VERSION 5.7 ;
  NOWIREEXTENSIONATPIN ON ;
  DIVIDERCHAR "/" ;
  BUSBITCHARS "[]" ;
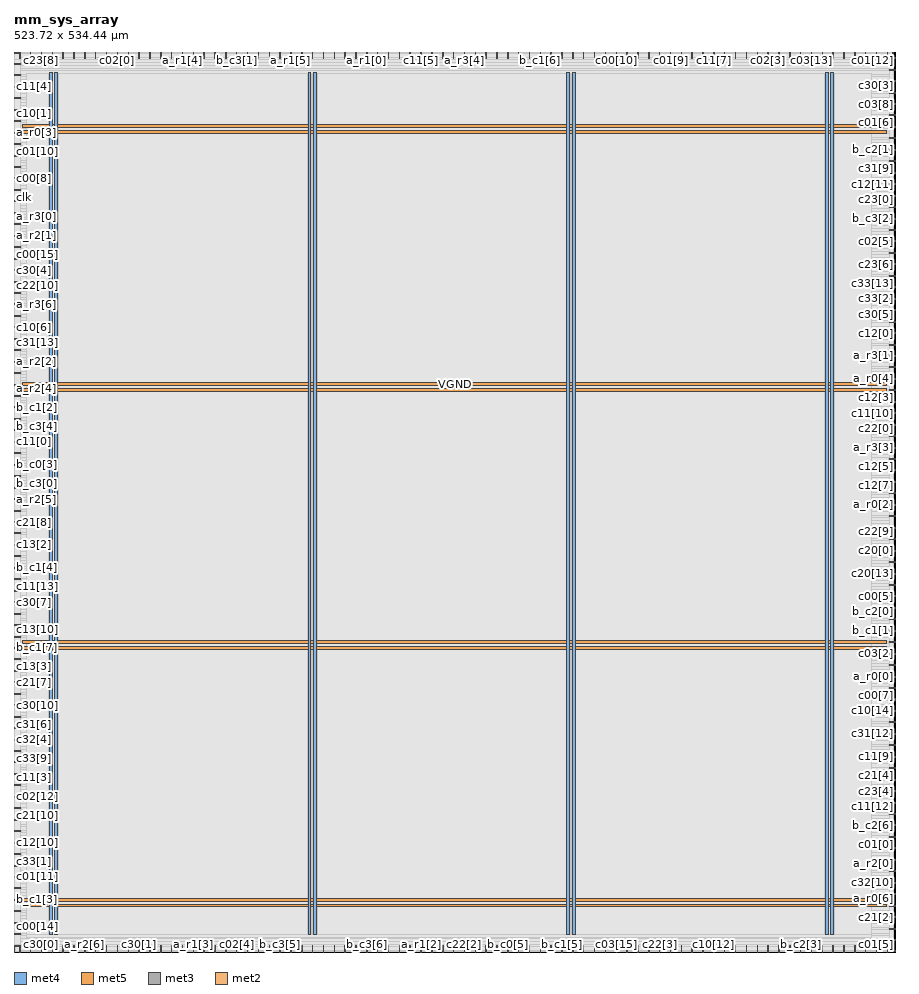
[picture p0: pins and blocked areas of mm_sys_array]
MACRO mm_sys_array
  CLASS BLOCK ;
  FOREIGN mm_sys_array ;
  ORIGIN 0.000 0.000 ;
  SIZE 523.720 BY 534.440 ;
  PIN VGND
    DIRECTION INOUT ;
    USE GROUND ;
    PORT
      LAYER met4 ;
        RECT 24.340 10.640 25.940 522.480 ;
    END
    PORT
      LAYER met4 ;
        RECT 177.940 10.640 179.540 522.480 ;
    END
    PORT
      LAYER met4 ;
        RECT 331.540 10.640 333.140 522.480 ;
    END
    PORT
      LAYER met4 ;
        RECT 485.140 10.640 486.740 522.480 ;
    END
    PORT
      LAYER met5 ;
        RECT 5.280 30.030 518.200 31.630 ;
    END
    PORT
      LAYER met5 ;
        RECT 5.280 183.210 518.200 184.810 ;
    END
    PORT
      LAYER met5 ;
        RECT 5.280 336.390 518.200 337.990 ;
    END
    PORT
      LAYER met5 ;
        RECT 5.280 489.570 518.200 491.170 ;
    END
  END VGND
  PIN VPWR
    DIRECTION INOUT ;
    USE POWER ;
    PORT
      LAYER met4 ;
        RECT 21.040 10.640 22.640 522.480 ;
    END
    PORT
      LAYER met4 ;
        RECT 174.640 10.640 176.240 522.480 ;
    END
    PORT
      LAYER met4 ;
        RECT 328.240 10.640 329.840 522.480 ;
    END
    PORT
      LAYER met4 ;
        RECT 481.840 10.640 483.440 522.480 ;
    END
    PORT
      LAYER met5 ;
        RECT 5.280 26.730 518.200 28.330 ;
    END
    PORT
      LAYER met5 ;
        RECT 5.280 179.910 518.200 181.510 ;
    END
    PORT
      LAYER met5 ;
        RECT 5.280 333.090 518.200 334.690 ;
    END
    PORT
      LAYER met5 ;
        RECT 5.280 486.270 518.200 487.870 ;
    END
  END VPWR
  PIN a_r0[0]
    DIRECTION INPUT ;
    USE SIGNAL ;
    ANTENNAGATEAREA 0.426000 ;
    PORT
      LAYER met3 ;
        RECT 519.720 163.240 523.720 163.840 ;
    END
  END a_r0[0]
  PIN a_r0[1]
    DIRECTION INPUT ;
    USE SIGNAL ;
    ANTENNAGATEAREA 0.247500 ;
    PORT
      LAYER met3 ;
        RECT 519.720 217.640 523.720 218.240 ;
    END
  END a_r0[1]
  PIN a_r0[2]
    DIRECTION INPUT ;
    USE SIGNAL ;
    ANTENNAGATEAREA 0.247500 ;
    PORT
      LAYER met3 ;
        RECT 519.720 265.240 523.720 265.840 ;
    END
  END a_r0[2]
  PIN a_r0[3]
    DIRECTION INPUT ;
    USE SIGNAL ;
    ANTENNAGATEAREA 0.426000 ;
    PORT
      LAYER met3 ;
        RECT 0.000 486.240 4.000 486.840 ;
    END
  END a_r0[3]
  PIN a_r0[4]
    DIRECTION INPUT ;
    USE SIGNAL ;
    ANTENNAGATEAREA 0.426000 ;
    PORT
      LAYER met3 ;
        RECT 519.720 340.040 523.720 340.640 ;
    END
  END a_r0[4]
  PIN a_r0[5]
    DIRECTION INPUT ;
    USE SIGNAL ;
    ANTENNAGATEAREA 0.247500 ;
    PORT
      LAYER met3 ;
        RECT 0.000 234.640 4.000 235.240 ;
    END
  END a_r0[5]
  PIN a_r0[6]
    DIRECTION INPUT ;
    USE SIGNAL ;
    ANTENNAGATEAREA 0.247500 ;
    PORT
      LAYER met3 ;
        RECT 519.720 27.240 523.720 27.840 ;
    END
  END a_r0[6]
  PIN a_r0[7]
    DIRECTION INPUT ;
    USE SIGNAL ;
    ANTENNAGATEAREA 0.247500 ;
    PORT
      LAYER met3 ;
        RECT 519.720 6.840 523.720 7.440 ;
    END
  END a_r0[7]
  PIN a_r1[0]
    DIRECTION INPUT ;
    USE SIGNAL ;
    ANTENNAGATEAREA 0.196500 ;
    PORT
      LAYER met2 ;
        RECT 209.390 530.440 209.670 534.440 ;
    END
  END a_r1[0]
  PIN a_r1[1]
    DIRECTION INPUT ;
    USE SIGNAL ;
    ANTENNAGATEAREA 0.213000 ;
    PORT
      LAYER met3 ;
        RECT 0.000 200.640 4.000 201.240 ;
    END
  END a_r1[1]
  PIN a_r1[2]
    DIRECTION INPUT ;
    USE SIGNAL ;
    ANTENNAGATEAREA 0.213000 ;
    PORT
      LAYER met2 ;
        RECT 241.590 0.000 241.870 4.000 ;
    END
  END a_r1[2]
  PIN a_r1[3]
    DIRECTION INPUT ;
    USE SIGNAL ;
    ANTENNAGATEAREA 0.159000 ;
    PORT
      LAYER met2 ;
        RECT 106.350 0.000 106.630 4.000 ;
    END
  END a_r1[3]
  PIN a_r1[4]
    DIRECTION INPUT ;
    USE SIGNAL ;
    ANTENNAGATEAREA 0.196500 ;
    PORT
      LAYER met2 ;
        RECT 99.910 530.440 100.190 534.440 ;
    END
  END a_r1[4]
  PIN a_r1[5]
    DIRECTION INPUT ;
    USE SIGNAL ;
    ANTENNAGATEAREA 0.196500 ;
    PORT
      LAYER met2 ;
        RECT 164.310 530.440 164.590 534.440 ;
    END
  END a_r1[5]
  PIN a_r1[6]
    DIRECTION INPUT ;
    USE SIGNAL ;
    ANTENNAGATEAREA 0.159000 ;
    PORT
      LAYER met2 ;
        RECT 144.990 0.000 145.270 4.000 ;
    END
  END a_r1[6]
  PIN a_r1[7]
    DIRECTION INPUT ;
    USE SIGNAL ;
    ANTENNAGATEAREA 0.159000 ;
    PORT
      LAYER met2 ;
        RECT 138.550 0.000 138.830 4.000 ;
    END
  END a_r1[7]
  PIN a_r2[0]
    DIRECTION INPUT ;
    USE SIGNAL ;
    ANTENNAGATEAREA 0.213000 ;
    PORT
      LAYER met3 ;
        RECT 519.720 47.640 523.720 48.240 ;
    END
  END a_r2[0]
  PIN a_r2[1]
    DIRECTION INPUT ;
    USE SIGNAL ;
    ANTENNAGATEAREA 0.196500 ;
    PORT
      LAYER met3 ;
        RECT 0.000 425.040 4.000 425.640 ;
    END
  END a_r2[1]
  PIN a_r2[2]
    DIRECTION INPUT ;
    USE SIGNAL ;
    ANTENNAGATEAREA 0.196500 ;
    PORT
      LAYER met3 ;
        RECT 0.000 350.240 4.000 350.840 ;
    END
  END a_r2[2]
  PIN a_r2[3]
    DIRECTION INPUT ;
    USE SIGNAL ;
    ANTENNAGATEAREA 0.196500 ;
    PORT
      LAYER met2 ;
        RECT 22.630 0.000 22.910 4.000 ;
    END
  END a_r2[3]
  PIN a_r2[4]
    DIRECTION INPUT ;
    USE SIGNAL ;
    ANTENNAGATEAREA 0.196500 ;
    PORT
      LAYER met3 ;
        RECT 0.000 329.840 4.000 330.440 ;
    END
  END a_r2[4]
  PIN a_r2[5]
    DIRECTION INPUT ;
    USE SIGNAL ;
    ANTENNAGATEAREA 0.196500 ;
    PORT
      LAYER met3 ;
        RECT 0.000 268.640 4.000 269.240 ;
    END
  END a_r2[5]
  PIN a_r2[6]
    DIRECTION INPUT ;
    USE SIGNAL ;
    ANTENNAGATEAREA 0.196500 ;
    PORT
      LAYER met2 ;
        RECT 41.950 0.000 42.230 4.000 ;
    END
  END a_r2[6]
  PIN a_r2[7]
    DIRECTION INPUT ;
    USE SIGNAL ;
    ANTENNAGATEAREA 0.196500 ;
    PORT
      LAYER met2 ;
        RECT 170.750 530.440 171.030 534.440 ;
    END
  END a_r2[7]
  PIN a_r3[0]
    DIRECTION INPUT ;
    USE SIGNAL ;
    ANTENNAGATEAREA 0.196500 ;
    PORT
      LAYER met3 ;
        RECT 0.000 431.840 4.000 432.440 ;
    END
  END a_r3[0]
  PIN a_r3[1]
    DIRECTION INPUT ;
    USE SIGNAL ;
    ANTENNAGATEAREA 0.159000 ;
    PORT
      LAYER met3 ;
        RECT 519.720 353.640 523.720 354.240 ;
    END
  END a_r3[1]
  PIN a_r3[2]
    DIRECTION INPUT ;
    USE SIGNAL ;
    ANTENNAGATEAREA 0.196500 ;
    PORT
      LAYER met3 ;
        RECT 0.000 309.440 4.000 310.040 ;
    END
  END a_r3[2]
  PIN a_r3[3]
    DIRECTION INPUT ;
    USE SIGNAL ;
    ANTENNAGATEAREA 0.213000 ;
    PORT
      LAYER met3 ;
        RECT 519.720 299.240 523.720 299.840 ;
    END
  END a_r3[3]
  PIN a_r3[4]
    DIRECTION INPUT ;
    USE SIGNAL ;
    ANTENNAGATEAREA 0.213000 ;
    PORT
      LAYER met2 ;
        RECT 267.350 530.440 267.630 534.440 ;
    END
  END a_r3[4]
  PIN a_r3[5]
    DIRECTION INPUT ;
    USE SIGNAL ;
    ANTENNAGATEAREA 0.159000 ;
    PORT
      LAYER met3 ;
        RECT 519.720 380.840 523.720 381.440 ;
    END
  END a_r3[5]
  PIN a_r3[6]
    DIRECTION INPUT ;
    USE SIGNAL ;
    ANTENNAGATEAREA 0.196500 ;
    PORT
      LAYER met3 ;
        RECT 0.000 384.240 4.000 384.840 ;
    END
  END a_r3[6]
  PIN a_r3[7]
    DIRECTION INPUT ;
    USE SIGNAL ;
    ANTENNAGATEAREA 0.213000 ;
    PORT
      LAYER met2 ;
        RECT 3.310 0.000 3.590 4.000 ;
    END
  END a_r3[7]
  PIN b_c0[0]
    DIRECTION INPUT ;
    USE SIGNAL ;
    ANTENNAGATEAREA 0.247500 ;
    PORT
      LAYER met2 ;
        RECT 402.590 0.000 402.870 4.000 ;
    END
  END b_c0[0]
  PIN b_c0[1]
    DIRECTION INPUT ;
    USE SIGNAL ;
    ANTENNAGATEAREA 0.426000 ;
    PORT
      LAYER met2 ;
        RECT 93.470 530.440 93.750 534.440 ;
    END
  END b_c0[1]
  PIN b_c0[2]
    DIRECTION INPUT ;
    USE SIGNAL ;
    ANTENNAGATEAREA 0.159000 ;
    PORT
      LAYER met3 ;
        RECT 519.720 326.440 523.720 327.040 ;
    END
  END b_c0[2]
  PIN b_c0[3]
    DIRECTION INPUT ;
    USE SIGNAL ;
    ANTENNAGATEAREA 0.213000 ;
    PORT
      LAYER met3 ;
        RECT 0.000 289.040 4.000 289.640 ;
    END
  END b_c0[3]
  PIN b_c0[4]
    DIRECTION INPUT ;
    USE SIGNAL ;
    ANTENNAGATEAREA 0.247500 ;
    PORT
      LAYER met3 ;
        RECT 0.000 261.840 4.000 262.440 ;
    END
  END b_c0[4]
  PIN b_c0[5]
    DIRECTION INPUT ;
    USE SIGNAL ;
    ANTENNAGATEAREA 0.213000 ;
    PORT
      LAYER met2 ;
        RECT 293.110 0.000 293.390 4.000 ;
    END
  END b_c0[5]
  PIN b_c0[6]
    DIRECTION INPUT ;
    USE SIGNAL ;
    ANTENNAGATEAREA 0.247500 ;
    PORT
      LAYER met3 ;
        RECT 0.000 71.440 4.000 72.040 ;
    END
  END b_c0[6]
  PIN b_c0[7]
    DIRECTION INPUT ;
    USE SIGNAL ;
    ANTENNAGATEAREA 0.742500 ;
    PORT
      LAYER met3 ;
        RECT 519.720 54.440 523.720 55.040 ;
    END
  END b_c0[7]
  PIN b_c1[0]
    DIRECTION INPUT ;
    USE SIGNAL ;
    ANTENNAGATEAREA 0.247500 ;
    PORT
      LAYER met3 ;
        RECT 0.000 17.040 4.000 17.640 ;
    END
  END b_c1[0]
  PIN b_c1[1]
    DIRECTION INPUT ;
    USE SIGNAL ;
    ANTENNAGATEAREA 0.196500 ;
    PORT
      LAYER met3 ;
        RECT 519.720 190.440 523.720 191.040 ;
    END
  END b_c1[1]
  PIN b_c1[2]
    DIRECTION INPUT ;
    USE SIGNAL ;
    ANTENNAGATEAREA 0.213000 ;
    PORT
      LAYER met3 ;
        RECT 0.000 323.040 4.000 323.640 ;
    END
  END b_c1[2]
  PIN b_c1[3]
    DIRECTION INPUT ;
    USE SIGNAL ;
    ANTENNAGATEAREA 0.213000 ;
    PORT
      LAYER met3 ;
        RECT 0.000 30.640 4.000 31.240 ;
    END
  END b_c1[3]
  PIN b_c1[4]
    DIRECTION INPUT ;
    USE SIGNAL ;
    ANTENNAGATEAREA 0.159000 ;
    PORT
      LAYER met3 ;
        RECT 0.000 227.840 4.000 228.440 ;
    END
  END b_c1[4]
  PIN b_c1[5]
    DIRECTION INPUT ;
    USE SIGNAL ;
    ANTENNAGATEAREA 0.213000 ;
    PORT
      LAYER met2 ;
        RECT 325.310 0.000 325.590 4.000 ;
    END
  END b_c1[5]
  PIN b_c1[6]
    DIRECTION INPUT ;
    USE SIGNAL ;
    ANTENNAGATEAREA 0.126000 ;
    PORT
      LAYER met2 ;
        RECT 312.430 530.440 312.710 534.440 ;
    END
  END b_c1[6]
  PIN b_c1[7]
    DIRECTION INPUT ;
    USE SIGNAL ;
    ANTENNAGATEAREA 0.159000 ;
    PORT
      LAYER met3 ;
        RECT 0.000 180.240 4.000 180.840 ;
    END
  END b_c1[7]
  PIN b_c2[0]
    DIRECTION INPUT ;
    USE SIGNAL ;
    ANTENNAGATEAREA 0.196500 ;
    PORT
      LAYER met3 ;
        RECT 519.720 197.240 523.720 197.840 ;
    END
  END b_c2[0]
  PIN b_c2[1]
    DIRECTION INPUT ;
    USE SIGNAL ;
    ANTENNAGATEAREA 0.213000 ;
    PORT
      LAYER met3 ;
        RECT 519.720 476.040 523.720 476.640 ;
    END
  END b_c2[1]
  PIN b_c2[2]
    DIRECTION INPUT ;
    USE SIGNAL ;
    ANTENNAGATEAREA 0.213000 ;
    PORT
      LAYER met2 ;
        RECT 67.710 0.000 67.990 4.000 ;
    END
  END b_c2[2]
  PIN b_c2[3]
    DIRECTION INPUT ;
    USE SIGNAL ;
    ANTENNAGATEAREA 0.196500 ;
    PORT
      LAYER met2 ;
        RECT 466.990 0.000 467.270 4.000 ;
    END
  END b_c2[3]
  PIN b_c2[4]
    DIRECTION INPUT ;
    USE SIGNAL ;
    ANTENNAGATEAREA 0.196500 ;
    PORT
      LAYER met3 ;
        RECT 519.720 13.640 523.720 14.240 ;
    END
  END b_c2[4]
  PIN b_c2[5]
    DIRECTION INPUT ;
    USE SIGNAL ;
    ANTENNAGATEAREA 0.213000 ;
    PORT
      LAYER met2 ;
        RECT 318.870 0.000 319.150 4.000 ;
    END
  END b_c2[5]
  PIN b_c2[6]
    DIRECTION INPUT ;
    USE SIGNAL ;
    ANTENNAGATEAREA 0.196500 ;
    PORT
      LAYER met3 ;
        RECT 519.720 74.840 523.720 75.440 ;
    END
  END b_c2[6]
  PIN b_c2[7]
    DIRECTION INPUT ;
    USE SIGNAL ;
    ANTENNAGATEAREA 0.213000 ;
    PORT
      LAYER met2 ;
        RECT 215.830 530.440 216.110 534.440 ;
    END
  END b_c2[7]
  PIN b_c3[0]
    DIRECTION INPUT ;
    USE SIGNAL ;
    ANTENNAGATEAREA 0.196500 ;
    PORT
      LAYER met3 ;
        RECT 0.000 282.240 4.000 282.840 ;
    END
  END b_c3[0]
  PIN b_c3[1]
    DIRECTION INPUT ;
    USE SIGNAL ;
    ANTENNAGATEAREA 0.213000 ;
    PORT
      LAYER met2 ;
        RECT 132.110 530.440 132.390 534.440 ;
    END
  END b_c3[1]
  PIN b_c3[2]
    DIRECTION INPUT ;
    USE SIGNAL ;
    ANTENNAGATEAREA 0.213000 ;
    PORT
      LAYER met3 ;
        RECT 519.720 435.240 523.720 435.840 ;
    END
  END b_c3[2]
  PIN b_c3[3]
    DIRECTION INPUT ;
    USE SIGNAL ;
    ANTENNAGATEAREA 0.196500 ;
    PORT
      LAYER met3 ;
        RECT 0.000 275.440 4.000 276.040 ;
    END
  END b_c3[3]
  PIN b_c3[4]
    DIRECTION INPUT ;
    USE SIGNAL ;
    ANTENNAGATEAREA 0.196500 ;
    PORT
      LAYER met3 ;
        RECT 0.000 316.240 4.000 316.840 ;
    END
  END b_c3[4]
  PIN b_c3[5]
    DIRECTION INPUT ;
    USE SIGNAL ;
    ANTENNAGATEAREA 0.196500 ;
    PORT
      LAYER met2 ;
        RECT 157.870 0.000 158.150 4.000 ;
    END
  END b_c3[5]
  PIN b_c3[6]
    DIRECTION INPUT ;
    USE SIGNAL ;
    ANTENNAGATEAREA 0.196500 ;
    PORT
      LAYER met2 ;
        RECT 209.390 0.000 209.670 4.000 ;
    END
  END b_c3[6]
  PIN b_c3[7]
    DIRECTION INPUT ;
    USE SIGNAL ;
    ANTENNAGATEAREA 0.196500 ;
    PORT
      LAYER met2 ;
        RECT 202.950 0.000 203.230 4.000 ;
    END
  END b_c3[7]
  PIN c00[0]
    DIRECTION OUTPUT TRISTATE ;
    USE SIGNAL ;
    ANTENNADIFFAREA 0.795200 ;
    PORT
      LAYER met2 ;
        RECT 61.270 0.000 61.550 4.000 ;
    END
  END c00[0]
  PIN c00[10]
    DIRECTION OUTPUT TRISTATE ;
    USE SIGNAL ;
    ANTENNADIFFAREA 0.795200 ;
    PORT
      LAYER met2 ;
        RECT 357.510 530.440 357.790 534.440 ;
    END
  END c00[10]
  PIN c00[11]
    DIRECTION OUTPUT TRISTATE ;
    USE SIGNAL ;
    ANTENNADIFFAREA 0.795200 ;
    PORT
      LAYER met2 ;
        RECT 473.430 0.000 473.710 4.000 ;
    END
  END c00[11]
  PIN c00[12]
    DIRECTION OUTPUT TRISTATE ;
    USE SIGNAL ;
    ANTENNADIFFAREA 0.795200 ;
    PORT
      LAYER met3 ;
        RECT 0.000 3.440 4.000 4.040 ;
    END
  END c00[12]
  PIN c00[13]
    DIRECTION OUTPUT TRISTATE ;
    USE SIGNAL ;
    ANTENNADIFFAREA 0.795200 ;
    PORT
      LAYER met3 ;
        RECT 519.720 88.440 523.720 89.040 ;
    END
  END c00[13]
  PIN c00[14]
    DIRECTION OUTPUT TRISTATE ;
    USE SIGNAL ;
    ANTENNADIFFAREA 0.795200 ;
    PORT
      LAYER met3 ;
        RECT 0.000 10.240 4.000 10.840 ;
    END
  END c00[14]
  PIN c00[15]
    DIRECTION OUTPUT TRISTATE ;
    USE SIGNAL ;
    ANTENNADIFFAREA 0.795200 ;
    PORT
      LAYER met3 ;
        RECT 0.000 418.240 4.000 418.840 ;
    END
  END c00[15]
  PIN c00[1]
    DIRECTION OUTPUT TRISTATE ;
    USE SIGNAL ;
    ANTENNADIFFAREA 0.795200 ;
    PORT
      LAYER met2 ;
        RECT 144.990 530.440 145.270 534.440 ;
    END
  END c00[1]
  PIN c00[2]
    DIRECTION OUTPUT TRISTATE ;
    USE SIGNAL ;
    ANTENNADIFFAREA 0.795200 ;
    PORT
      LAYER met2 ;
        RECT 74.150 530.440 74.430 534.440 ;
    END
  END c00[2]
  PIN c00[3]
    DIRECTION OUTPUT TRISTATE ;
    USE SIGNAL ;
    ANTENNADIFFAREA 0.795200 ;
    PORT
      LAYER met3 ;
        RECT 0.000 112.240 4.000 112.840 ;
    END
  END c00[3]
  PIN c00[4]
    DIRECTION OUTPUT TRISTATE ;
    USE SIGNAL ;
    ANTENNADIFFAREA 0.795200 ;
    PORT
      LAYER met2 ;
        RECT 125.670 0.000 125.950 4.000 ;
    END
  END c00[4]
  PIN c00[5]
    DIRECTION OUTPUT TRISTATE ;
    USE SIGNAL ;
    ANTENNADIFFAREA 0.445500 ;
    PORT
      LAYER met3 ;
        RECT 519.720 210.840 523.720 211.440 ;
    END
  END c00[5]
  PIN c00[6]
    DIRECTION OUTPUT TRISTATE ;
    USE SIGNAL ;
    ANTENNADIFFAREA 0.445500 ;
    PORT
      LAYER met2 ;
        RECT 202.950 530.440 203.230 534.440 ;
    END
  END c00[6]
  PIN c00[7]
    DIRECTION OUTPUT TRISTATE ;
    USE SIGNAL ;
    ANTENNADIFFAREA 0.795200 ;
    PORT
      LAYER met3 ;
        RECT 519.720 156.440 523.720 157.040 ;
    END
  END c00[7]
  PIN c00[8]
    DIRECTION OUTPUT TRISTATE ;
    USE SIGNAL ;
    ANTENNADIFFAREA 0.795200 ;
    PORT
      LAYER met3 ;
        RECT 0.000 459.040 4.000 459.640 ;
    END
  END c00[8]
  PIN c00[9]
    DIRECTION OUTPUT TRISTATE ;
    USE SIGNAL ;
    ANTENNADIFFAREA 0.445500 ;
    PORT
      LAYER met3 ;
        RECT 519.720 516.840 523.720 517.440 ;
    END
  END c00[9]
  PIN c01[0]
    DIRECTION OUTPUT TRISTATE ;
    USE SIGNAL ;
    ANTENNADIFFAREA 0.795200 ;
    PORT
      LAYER met3 ;
        RECT 519.720 68.040 523.720 68.640 ;
    END
  END c01[0]
  PIN c01[10]
    DIRECTION OUTPUT TRISTATE ;
    USE SIGNAL ;
    ANTENNADIFFAREA 0.795200 ;
    PORT
      LAYER met3 ;
        RECT 0.000 479.440 4.000 480.040 ;
    END
  END c01[10]
  PIN c01[11]
    DIRECTION OUTPUT TRISTATE ;
    USE SIGNAL ;
    ANTENNADIFFAREA 0.795200 ;
    PORT
      LAYER met3 ;
        RECT 0.000 44.240 4.000 44.840 ;
    END
  END c01[11]
  PIN c01[12]
    DIRECTION OUTPUT TRISTATE ;
    USE SIGNAL ;
    ANTENNADIFFAREA 0.795200 ;
    PORT
      LAYER met2 ;
        RECT 518.510 530.440 518.790 534.440 ;
    END
  END c01[12]
  PIN c01[13]
    DIRECTION OUTPUT TRISTATE ;
    USE SIGNAL ;
    ANTENNADIFFAREA 0.795200 ;
    PORT
      LAYER met2 ;
        RECT 479.870 0.000 480.150 4.000 ;
    END
  END c01[13]
  PIN c01[14]
    DIRECTION OUTPUT TRISTATE ;
    USE SIGNAL ;
    ANTENNADIFFAREA 0.795200 ;
    PORT
      LAYER met2 ;
        RECT 222.270 530.440 222.550 534.440 ;
    END
  END c01[14]
  PIN c01[15]
    DIRECTION OUTPUT TRISTATE ;
    USE SIGNAL ;
    ANTENNADIFFAREA 0.795200 ;
    PORT
      LAYER met2 ;
        RECT 228.710 0.000 228.990 4.000 ;
    END
  END c01[15]
  PIN c01[1]
    DIRECTION OUTPUT TRISTATE ;
    USE SIGNAL ;
    ANTENNADIFFAREA 0.795200 ;
    PORT
      LAYER met2 ;
        RECT 521.730 530.440 522.010 534.440 ;
    END
  END c01[1]
  PIN c01[2]
    DIRECTION OUTPUT TRISTATE ;
    USE SIGNAL ;
    ANTENNADIFFAREA 0.795200 ;
    PORT
      LAYER met2 ;
        RECT 512.070 530.440 512.350 534.440 ;
    END
  END c01[2]
  PIN c01[3]
    DIRECTION OUTPUT TRISTATE ;
    USE SIGNAL ;
    ANTENNADIFFAREA 0.795200 ;
    PORT
      LAYER met2 ;
        RECT 460.550 0.000 460.830 4.000 ;
    END
  END c01[3]
  PIN c01[4]
    DIRECTION OUTPUT TRISTATE ;
    USE SIGNAL ;
    ANTENNADIFFAREA 0.795200 ;
    PORT
      LAYER met2 ;
        RECT 125.670 530.440 125.950 534.440 ;
    END
  END c01[4]
  PIN c01[5]
    DIRECTION OUTPUT TRISTATE ;
    USE SIGNAL ;
    ANTENNADIFFAREA 0.795200 ;
    PORT
      LAYER met2 ;
        RECT 512.070 0.000 512.350 4.000 ;
    END
  END c01[5]
  PIN c01[6]
    DIRECTION OUTPUT TRISTATE ;
    USE SIGNAL ;
    ANTENNADIFFAREA 0.795200 ;
    PORT
      LAYER met3 ;
        RECT 519.720 496.440 523.720 497.040 ;
    END
  END c01[6]
  PIN c01[7]
    DIRECTION OUTPUT TRISTATE ;
    USE SIGNAL ;
    ANTENNADIFFAREA 0.445500 ;
    PORT
      LAYER met2 ;
        RECT 499.190 530.440 499.470 534.440 ;
    END
  END c01[7]
  PIN c01[8]
    DIRECTION OUTPUT TRISTATE ;
    USE SIGNAL ;
    ANTENNADIFFAREA 0.795200 ;
    PORT
      LAYER met2 ;
        RECT 177.190 0.000 177.470 4.000 ;
    END
  END c01[8]
  PIN c01[9]
    DIRECTION OUTPUT TRISTATE ;
    USE SIGNAL ;
    ANTENNADIFFAREA 0.795200 ;
    PORT
      LAYER met2 ;
        RECT 389.710 530.440 389.990 534.440 ;
    END
  END c01[9]
  PIN c02[0]
    DIRECTION OUTPUT TRISTATE ;
    USE SIGNAL ;
    ANTENNADIFFAREA 0.795200 ;
    PORT
      LAYER met2 ;
        RECT 61.270 530.440 61.550 534.440 ;
    END
  END c02[0]
  PIN c02[10]
    DIRECTION OUTPUT TRISTATE ;
    USE SIGNAL ;
    ANTENNADIFFAREA 0.445500 ;
    PORT
      LAYER met3 ;
        RECT 519.720 312.840 523.720 313.440 ;
    END
  END c02[10]
  PIN c02[11]
    DIRECTION OUTPUT TRISTATE ;
    USE SIGNAL ;
    ANTENNADIFFAREA 0.795200 ;
    PORT
      LAYER met3 ;
        RECT 519.720 34.040 523.720 34.640 ;
    END
  END c02[11]
  PIN c02[12]
    DIRECTION OUTPUT TRISTATE ;
    USE SIGNAL ;
    ANTENNADIFFAREA 0.795200 ;
    PORT
      LAYER met3 ;
        RECT 0.000 91.840 4.000 92.440 ;
    END
  END c02[12]
  PIN c02[13]
    DIRECTION OUTPUT TRISTATE ;
    USE SIGNAL ;
    ANTENNADIFFAREA 0.795200 ;
    PORT
      LAYER met2 ;
        RECT 447.670 0.000 447.950 4.000 ;
    END
  END c02[13]
  PIN c02[14]
    DIRECTION OUTPUT TRISTATE ;
    USE SIGNAL ;
    ANTENNADIFFAREA 0.445500 ;
    PORT
      LAYER met2 ;
        RECT 9.750 530.440 10.030 534.440 ;
    END
  END c02[14]
  PIN c02[15]
    DIRECTION OUTPUT TRISTATE ;
    USE SIGNAL ;
    ANTENNADIFFAREA 0.795200 ;
    PORT
      LAYER met2 ;
        RECT 389.710 0.000 389.990 4.000 ;
    END
  END c02[15]
  PIN c02[1]
    DIRECTION OUTPUT TRISTATE ;
    USE SIGNAL ;
    ANTENNADIFFAREA 0.795200 ;
    PORT
      LAYER met2 ;
        RECT 35.510 530.440 35.790 534.440 ;
    END
  END c02[1]
  PIN c02[2]
    DIRECTION OUTPUT TRISTATE ;
    USE SIGNAL ;
    ANTENNADIFFAREA 0.795200 ;
    PORT
      LAYER met3 ;
        RECT 519.720 530.440 523.720 531.040 ;
    END
  END c02[2]
  PIN c02[3]
    DIRECTION OUTPUT TRISTATE ;
    USE SIGNAL ;
    ANTENNADIFFAREA 0.795200 ;
    PORT
      LAYER met2 ;
        RECT 447.670 530.440 447.950 534.440 ;
    END
  END c02[3]
  PIN c02[4]
    DIRECTION OUTPUT TRISTATE ;
    USE SIGNAL ;
    ANTENNADIFFAREA 0.795200 ;
    PORT
      LAYER met2 ;
        RECT 132.110 0.000 132.390 4.000 ;
    END
  END c02[4]
  PIN c02[5]
    DIRECTION OUTPUT TRISTATE ;
    USE SIGNAL ;
    ANTENNADIFFAREA 0.445500 ;
    PORT
      LAYER met3 ;
        RECT 519.720 421.640 523.720 422.240 ;
    END
  END c02[5]
  PIN c02[6]
    DIRECTION OUTPUT TRISTATE ;
    USE SIGNAL ;
    ANTENNADIFFAREA 0.795200 ;
    PORT
      LAYER met2 ;
        RECT 299.550 530.440 299.830 534.440 ;
    END
  END c02[6]
  PIN c02[7]
    DIRECTION OUTPUT TRISTATE ;
    USE SIGNAL ;
    ANTENNADIFFAREA 0.795200 ;
    PORT
      LAYER met2 ;
        RECT 286.670 0.000 286.950 4.000 ;
    END
  END c02[7]
  PIN c02[8]
    DIRECTION OUTPUT TRISTATE ;
    USE SIGNAL ;
    ANTENNADIFFAREA 0.445500 ;
    PORT
      LAYER met3 ;
        RECT 519.720 428.440 523.720 429.040 ;
    END
  END c02[8]
  PIN c02[9]
    DIRECTION OUTPUT TRISTATE ;
    USE SIGNAL ;
    ANTENNADIFFAREA 0.795200 ;
    PORT
      LAYER met2 ;
        RECT 170.750 0.000 171.030 4.000 ;
    END
  END c02[9]
  PIN c03[0]
    DIRECTION OUTPUT TRISTATE ;
    USE SIGNAL ;
    ANTENNADIFFAREA 0.795200 ;
    PORT
      LAYER met2 ;
        RECT 93.470 0.000 93.750 4.000 ;
    END
  END c03[0]
  PIN c03[10]
    DIRECTION OUTPUT TRISTATE ;
    USE SIGNAL ;
    ANTENNADIFFAREA 0.445500 ;
    PORT
      LAYER met3 ;
        RECT 519.720 346.840 523.720 347.440 ;
    END
  END c03[10]
  PIN c03[11]
    DIRECTION OUTPUT TRISTATE ;
    USE SIGNAL ;
    ANTENNADIFFAREA 0.795200 ;
    PORT
      LAYER met2 ;
        RECT 505.630 0.000 505.910 4.000 ;
    END
  END c03[11]
  PIN c03[12]
    DIRECTION OUTPUT TRISTATE ;
    USE SIGNAL ;
    ANTENNADIFFAREA 0.795200 ;
    PORT
      LAYER met3 ;
        RECT 0.000 23.840 4.000 24.440 ;
    END
  END c03[12]
  PIN c03[13]
    DIRECTION OUTPUT TRISTATE ;
    USE SIGNAL ;
    ANTENNADIFFAREA 0.795200 ;
    PORT
      LAYER met2 ;
        RECT 473.430 530.440 473.710 534.440 ;
    END
  END c03[13]
  PIN c03[14]
    DIRECTION OUTPUT TRISTATE ;
    USE SIGNAL ;
    ANTENNADIFFAREA 0.795200 ;
    PORT
      LAYER met2 ;
        RECT 235.150 0.000 235.430 4.000 ;
    END
  END c03[14]
  PIN c03[15]
    DIRECTION OUTPUT TRISTATE ;
    USE SIGNAL ;
    ANTENNADIFFAREA 0.795200 ;
    PORT
      LAYER met2 ;
        RECT 357.510 0.000 357.790 4.000 ;
    END
  END c03[15]
  PIN c03[1]
    DIRECTION OUTPUT TRISTATE ;
    USE SIGNAL ;
    ANTENNADIFFAREA 0.795200 ;
    PORT
      LAYER met2 ;
        RECT 151.430 530.440 151.710 534.440 ;
    END
  END c03[1]
  PIN c03[2]
    DIRECTION OUTPUT TRISTATE ;
    USE SIGNAL ;
    ANTENNADIFFAREA 0.445500 ;
    PORT
      LAYER met3 ;
        RECT 519.720 176.840 523.720 177.440 ;
    END
  END c03[2]
  PIN c03[3]
    DIRECTION OUTPUT TRISTATE ;
    USE SIGNAL ;
    ANTENNADIFFAREA 0.795200 ;
    PORT
      LAYER met2 ;
        RECT 260.910 530.440 261.190 534.440 ;
    END
  END c03[3]
  PIN c03[4]
    DIRECTION OUTPUT TRISTATE ;
    USE SIGNAL ;
    ANTENNADIFFAREA 0.795200 ;
    PORT
      LAYER met3 ;
        RECT 0.000 37.440 4.000 38.040 ;
    END
  END c03[4]
  PIN c03[5]
    DIRECTION OUTPUT TRISTATE ;
    USE SIGNAL ;
    ANTENNADIFFAREA 0.795200 ;
    PORT
      LAYER met2 ;
        RECT 370.390 530.440 370.670 534.440 ;
    END
  END c03[5]
  PIN c03[6]
    DIRECTION OUTPUT TRISTATE ;
    USE SIGNAL ;
    ANTENNADIFFAREA 0.795200 ;
    PORT
      LAYER met3 ;
        RECT 0.000 343.440 4.000 344.040 ;
    END
  END c03[6]
  PIN c03[7]
    DIRECTION OUTPUT TRISTATE ;
    USE SIGNAL ;
    ANTENNADIFFAREA 0.795200 ;
    PORT
      LAYER met3 ;
        RECT 0.000 166.640 4.000 167.240 ;
    END
  END c03[7]
  PIN c03[8]
    DIRECTION OUTPUT TRISTATE ;
    USE SIGNAL ;
    ANTENNADIFFAREA 0.795200 ;
    PORT
      LAYER met3 ;
        RECT 519.720 503.240 523.720 503.840 ;
    END
  END c03[8]
  PIN c03[9]
    DIRECTION OUTPUT TRISTATE ;
    USE SIGNAL ;
    ANTENNADIFFAREA 0.795200 ;
    PORT
      LAYER met3 ;
        RECT 0.000 472.640 4.000 473.240 ;
    END
  END c03[9]
  PIN c10[0]
    DIRECTION OUTPUT TRISTATE ;
    USE SIGNAL ;
    ANTENNADIFFAREA 0.795200 ;
    PORT
      LAYER met2 ;
        RECT 54.830 530.440 55.110 534.440 ;
    END
  END c10[0]
  PIN c10[10]
    DIRECTION OUTPUT TRISTATE ;
    USE SIGNAL ;
    ANTENNADIFFAREA 0.795200 ;
    PORT
      LAYER met2 ;
        RECT 434.790 530.440 435.070 534.440 ;
    END
  END c10[10]
  PIN c10[11]
    DIRECTION OUTPUT TRISTATE ;
    USE SIGNAL ;
    ANTENNADIFFAREA 0.795200 ;
    PORT
      LAYER met2 ;
        RECT 29.070 0.000 29.350 4.000 ;
    END
  END c10[11]
  PIN c10[12]
    DIRECTION OUTPUT TRISTATE ;
    USE SIGNAL ;
    ANTENNADIFFAREA 0.795200 ;
    PORT
      LAYER met2 ;
        RECT 415.470 0.000 415.750 4.000 ;
    END
  END c10[12]
  PIN c10[13]
    DIRECTION OUTPUT TRISTATE ;
    USE SIGNAL ;
    ANTENNADIFFAREA 0.795200 ;
    PORT
      LAYER met2 ;
        RECT 80.590 530.440 80.870 534.440 ;
    END
  END c10[13]
  PIN c10[14]
    DIRECTION OUTPUT TRISTATE ;
    USE SIGNAL ;
    ANTENNADIFFAREA 0.445500 ;
    PORT
      LAYER met3 ;
        RECT 519.720 142.840 523.720 143.440 ;
    END
  END c10[14]
  PIN c10[15]
    DIRECTION OUTPUT TRISTATE ;
    USE SIGNAL ;
    ANTENNADIFFAREA 0.795200 ;
    PORT
      LAYER met3 ;
        RECT 0.000 78.240 4.000 78.840 ;
    END
  END c10[15]
  PIN c10[1]
    DIRECTION OUTPUT TRISTATE ;
    USE SIGNAL ;
    ANTENNADIFFAREA 0.795200 ;
    PORT
      LAYER met3 ;
        RECT 0.000 493.040 4.000 493.640 ;
    END
  END c10[1]
  PIN c10[2]
    DIRECTION OUTPUT TRISTATE ;
    USE SIGNAL ;
    ANTENNADIFFAREA 0.795200 ;
    PORT
      LAYER met2 ;
        RECT 157.870 530.440 158.150 534.440 ;
    END
  END c10[2]
  PIN c10[3]
    DIRECTION OUTPUT TRISTATE ;
    USE SIGNAL ;
    ANTENNADIFFAREA 0.795200 ;
    PORT
      LAYER met2 ;
        RECT 331.750 530.440 332.030 534.440 ;
    END
  END c10[3]
  PIN c10[4]
    DIRECTION OUTPUT TRISTATE ;
    USE SIGNAL ;
    ANTENNADIFFAREA 0.795200 ;
    PORT
      LAYER met2 ;
        RECT 325.310 530.440 325.590 534.440 ;
    END
  END c10[4]
  PIN c10[5]
    DIRECTION OUTPUT TRISTATE ;
    USE SIGNAL ;
    ANTENNADIFFAREA 0.795200 ;
    PORT
      LAYER met3 ;
        RECT 0.000 411.440 4.000 412.040 ;
    END
  END c10[5]
  PIN c10[6]
    DIRECTION OUTPUT TRISTATE ;
    USE SIGNAL ;
    ANTENNADIFFAREA 0.795200 ;
    PORT
      LAYER met3 ;
        RECT 0.000 370.640 4.000 371.240 ;
    END
  END c10[6]
  PIN c10[7]
    DIRECTION OUTPUT TRISTATE ;
    USE SIGNAL ;
    ANTENNADIFFAREA 0.795200 ;
    PORT
      LAYER met3 ;
        RECT 0.000 438.640 4.000 439.240 ;
    END
  END c10[7]
  PIN c10[8]
    DIRECTION OUTPUT TRISTATE ;
    USE SIGNAL ;
    ANTENNADIFFAREA 0.795200 ;
    PORT
      LAYER met2 ;
        RECT 138.550 530.440 138.830 534.440 ;
    END
  END c10[8]
  PIN c10[9]
    DIRECTION OUTPUT TRISTATE ;
    USE SIGNAL ;
    ANTENNADIFFAREA 0.795200 ;
    PORT
      LAYER met2 ;
        RECT 428.350 0.000 428.630 4.000 ;
    END
  END c10[9]
  PIN c11[0]
    DIRECTION OUTPUT TRISTATE ;
    USE SIGNAL ;
    ANTENNADIFFAREA 0.795200 ;
    PORT
      LAYER met3 ;
        RECT 0.000 302.640 4.000 303.240 ;
    END
  END c11[0]
  PIN c11[10]
    DIRECTION OUTPUT TRISTATE ;
    USE SIGNAL ;
    ANTENNADIFFAREA 0.445500 ;
    PORT
      LAYER met3 ;
        RECT 519.720 319.640 523.720 320.240 ;
    END
  END c11[10]
  PIN c11[11]
    DIRECTION OUTPUT TRISTATE ;
    USE SIGNAL ;
    ANTENNADIFFAREA 0.795200 ;
    PORT
      LAYER met2 ;
        RECT 228.710 530.440 228.990 534.440 ;
    END
  END c11[11]
  PIN c11[12]
    DIRECTION OUTPUT TRISTATE ;
    USE SIGNAL ;
    ANTENNADIFFAREA 0.795200 ;
    PORT
      LAYER met3 ;
        RECT 519.720 81.640 523.720 82.240 ;
    END
  END c11[12]
  PIN c11[13]
    DIRECTION OUTPUT TRISTATE ;
    USE SIGNAL ;
    ANTENNADIFFAREA 0.795200 ;
    PORT
      LAYER met3 ;
        RECT 0.000 221.040 4.000 221.640 ;
    END
  END c11[13]
  PIN c11[14]
    DIRECTION OUTPUT TRISTATE ;
    USE SIGNAL ;
    ANTENNADIFFAREA 0.445500 ;
    PORT
      LAYER met3 ;
        RECT 519.720 183.640 523.720 184.240 ;
    END
  END c11[14]
  PIN c11[15]
    DIRECTION OUTPUT TRISTATE ;
    USE SIGNAL ;
    ANTENNADIFFAREA 0.795200 ;
    PORT
      LAYER met3 ;
        RECT 519.720 122.440 523.720 123.040 ;
    END
  END c11[15]
  PIN c11[1]
    DIRECTION OUTPUT TRISTATE ;
    USE SIGNAL ;
    ANTENNADIFFAREA 0.795200 ;
    PORT
      LAYER met2 ;
        RECT 312.430 0.000 312.710 4.000 ;
    END
  END c11[1]
  PIN c11[2]
    DIRECTION OUTPUT TRISTATE ;
    USE SIGNAL ;
    ANTENNADIFFAREA 0.795200 ;
    PORT
      LAYER met3 ;
        RECT 0.000 465.840 4.000 466.440 ;
    END
  END c11[2]
  PIN c11[3]
    DIRECTION OUTPUT TRISTATE ;
    USE SIGNAL ;
    ANTENNADIFFAREA 0.795200 ;
    PORT
      LAYER met3 ;
        RECT 0.000 98.640 4.000 99.240 ;
    END
  END c11[3]
  PIN c11[4]
    DIRECTION OUTPUT TRISTATE ;
    USE SIGNAL ;
    ANTENNADIFFAREA 0.795200 ;
    PORT
      LAYER met3 ;
        RECT 0.000 513.440 4.000 514.040 ;
    END
  END c11[4]
  PIN c11[5]
    DIRECTION OUTPUT TRISTATE ;
    USE SIGNAL ;
    ANTENNADIFFAREA 0.795200 ;
    PORT
      LAYER met2 ;
        RECT 241.590 530.440 241.870 534.440 ;
    END
  END c11[5]
  PIN c11[6]
    DIRECTION OUTPUT TRISTATE ;
    USE SIGNAL ;
    ANTENNADIFFAREA 0.795200 ;
    PORT
      LAYER met2 ;
        RECT 87.030 0.000 87.310 4.000 ;
    END
  END c11[6]
  PIN c11[7]
    DIRECTION OUTPUT TRISTATE ;
    USE SIGNAL ;
    ANTENNADIFFAREA 0.795200 ;
    PORT
      LAYER met2 ;
        RECT 415.470 530.440 415.750 534.440 ;
    END
  END c11[7]
  PIN c11[8]
    DIRECTION OUTPUT TRISTATE ;
    USE SIGNAL ;
    ANTENNADIFFAREA 0.795200 ;
    PORT
      LAYER met2 ;
        RECT 402.590 530.440 402.870 534.440 ;
    END
  END c11[8]
  PIN c11[9]
    DIRECTION OUTPUT TRISTATE ;
    USE SIGNAL ;
    ANTENNADIFFAREA 0.795200 ;
    PORT
      LAYER met3 ;
        RECT 519.720 115.640 523.720 116.240 ;
    END
  END c11[9]
  PIN c12[0]
    DIRECTION OUTPUT TRISTATE ;
    USE SIGNAL ;
    ANTENNADIFFAREA 0.445500 ;
    PORT
      LAYER met3 ;
        RECT 519.720 367.240 523.720 367.840 ;
    END
  END c12[0]
  PIN c12[10]
    DIRECTION OUTPUT TRISTATE ;
    USE SIGNAL ;
    ANTENNADIFFAREA 0.795200 ;
    PORT
      LAYER met3 ;
        RECT 0.000 64.640 4.000 65.240 ;
    END
  END c12[10]
  PIN c12[11]
    DIRECTION OUTPUT TRISTATE ;
    USE SIGNAL ;
    ANTENNADIFFAREA 0.795200 ;
    PORT
      LAYER met3 ;
        RECT 519.720 455.640 523.720 456.240 ;
    END
  END c12[11]
  PIN c12[12]
    DIRECTION OUTPUT TRISTATE ;
    USE SIGNAL ;
    ANTENNADIFFAREA 0.795200 ;
    PORT
      LAYER met2 ;
        RECT 119.230 0.000 119.510 4.000 ;
    END
  END c12[12]
  PIN c12[13]
    DIRECTION OUTPUT TRISTATE ;
    USE SIGNAL ;
    ANTENNADIFFAREA 0.795200 ;
    PORT
      LAYER met2 ;
        RECT 286.670 530.440 286.950 534.440 ;
    END
  END c12[13]
  PIN c12[14]
    DIRECTION OUTPUT TRISTATE ;
    USE SIGNAL ;
    ANTENNADIFFAREA 0.795200 ;
    PORT
      LAYER met3 ;
        RECT 0.000 527.040 4.000 527.640 ;
    END
  END c12[14]
  PIN c12[15]
    DIRECTION OUTPUT TRISTATE ;
    USE SIGNAL ;
    ANTENNADIFFAREA 0.795200 ;
    PORT
      LAYER met2 ;
        RECT 196.510 530.440 196.790 534.440 ;
    END
  END c12[15]
  PIN c12[1]
    DIRECTION OUTPUT TRISTATE ;
    USE SIGNAL ;
    ANTENNADIFFAREA 0.795200 ;
    PORT
      LAYER met3 ;
        RECT 0.000 397.840 4.000 398.440 ;
    END
  END c12[1]
  PIN c12[2]
    DIRECTION OUTPUT TRISTATE ;
    USE SIGNAL ;
    ANTENNADIFFAREA 0.795200 ;
    PORT
      LAYER met3 ;
        RECT 0.000 363.840 4.000 364.440 ;
    END
  END c12[2]
  PIN c12[3]
    DIRECTION OUTPUT TRISTATE ;
    USE SIGNAL ;
    ANTENNADIFFAREA 0.445500 ;
    PORT
      LAYER met3 ;
        RECT 519.720 333.240 523.720 333.840 ;
    END
  END c12[3]
  PIN c12[4]
    DIRECTION OUTPUT TRISTATE ;
    USE SIGNAL ;
    ANTENNADIFFAREA 0.795200 ;
    PORT
      LAYER met3 ;
        RECT 519.720 360.440 523.720 361.040 ;
    END
  END c12[4]
  PIN c12[5]
    DIRECTION OUTPUT TRISTATE ;
    USE SIGNAL ;
    ANTENNADIFFAREA 0.445500 ;
    PORT
      LAYER met3 ;
        RECT 519.720 292.440 523.720 293.040 ;
    END
  END c12[5]
  PIN c12[6]
    DIRECTION OUTPUT TRISTATE ;
    USE SIGNAL ;
    ANTENNADIFFAREA 0.445500 ;
    PORT
      LAYER met2 ;
        RECT 112.790 530.440 113.070 534.440 ;
    END
  END c12[6]
  PIN c12[7]
    DIRECTION OUTPUT TRISTATE ;
    USE SIGNAL ;
    ANTENNADIFFAREA 0.795200 ;
    PORT
      LAYER met3 ;
        RECT 519.720 272.040 523.720 272.640 ;
    END
  END c12[7]
  PIN c12[8]
    DIRECTION OUTPUT TRISTATE ;
    USE SIGNAL ;
    ANTENNADIFFAREA 0.795200 ;
    PORT
      LAYER met2 ;
        RECT 215.830 0.000 216.110 4.000 ;
    END
  END c12[8]
  PIN c12[9]
    DIRECTION OUTPUT TRISTATE ;
    USE SIGNAL ;
    ANTENNADIFFAREA 0.445500 ;
    PORT
      LAYER met3 ;
        RECT 519.720 414.840 523.720 415.440 ;
    END
  END c12[9]
  PIN c13[0]
    DIRECTION OUTPUT TRISTATE ;
    USE SIGNAL ;
    ANTENNADIFFAREA 0.795200 ;
    PORT
      LAYER met2 ;
        RECT 376.830 530.440 377.110 534.440 ;
    END
  END c13[0]
  PIN c13[10]
    DIRECTION OUTPUT TRISTATE ;
    USE SIGNAL ;
    ANTENNADIFFAREA 0.795200 ;
    PORT
      LAYER met3 ;
        RECT 0.000 187.040 4.000 187.640 ;
    END
  END c13[10]
  PIN c13[11]
    DIRECTION OUTPUT TRISTATE ;
    USE SIGNAL ;
    ANTENNADIFFAREA 0.795200 ;
    PORT
      LAYER met2 ;
        RECT 338.190 530.440 338.470 534.440 ;
    END
  END c13[11]
  PIN c13[12]
    DIRECTION OUTPUT TRISTATE ;
    USE SIGNAL ;
    ANTENNADIFFAREA 0.795200 ;
    PORT
      LAYER met2 ;
        RECT 222.270 0.000 222.550 4.000 ;
    END
  END c13[12]
  PIN c13[13]
    DIRECTION OUTPUT TRISTATE ;
    USE SIGNAL ;
    ANTENNADIFFAREA 0.795200 ;
    PORT
      LAYER met2 ;
        RECT 87.030 530.440 87.310 534.440 ;
    END
  END c13[13]
  PIN c13[14]
    DIRECTION OUTPUT TRISTATE ;
    USE SIGNAL ;
    ANTENNADIFFAREA 0.445500 ;
    PORT
      LAYER met3 ;
        RECT 519.720 394.440 523.720 395.040 ;
    END
  END c13[14]
  PIN c13[15]
    DIRECTION OUTPUT TRISTATE ;
    USE SIGNAL ;
    ANTENNADIFFAREA 0.795200 ;
    PORT
      LAYER met2 ;
        RECT 492.750 0.000 493.030 4.000 ;
    END
  END c13[15]
  PIN c13[1]
    DIRECTION OUTPUT TRISTATE ;
    USE SIGNAL ;
    ANTENNADIFFAREA 0.795200 ;
    PORT
      LAYER met2 ;
        RECT 396.150 530.440 396.430 534.440 ;
    END
  END c13[1]
  PIN c13[2]
    DIRECTION OUTPUT TRISTATE ;
    USE SIGNAL ;
    ANTENNADIFFAREA 0.795200 ;
    PORT
      LAYER met3 ;
        RECT 0.000 241.440 4.000 242.040 ;
    END
  END c13[2]
  PIN c13[3]
    DIRECTION OUTPUT TRISTATE ;
    USE SIGNAL ;
    ANTENNADIFFAREA 0.795200 ;
    PORT
      LAYER met3 ;
        RECT 0.000 173.440 4.000 174.040 ;
    END
  END c13[3]
  PIN c13[4]
    DIRECTION OUTPUT TRISTATE ;
    USE SIGNAL ;
    ANTENNADIFFAREA 0.795200 ;
    PORT
      LAYER met2 ;
        RECT 190.070 0.000 190.350 4.000 ;
    END
  END c13[4]
  PIN c13[5]
    DIRECTION OUTPUT TRISTATE ;
    USE SIGNAL ;
    ANTENNADIFFAREA 0.795200 ;
    PORT
      LAYER met2 ;
        RECT 273.790 530.440 274.070 534.440 ;
    END
  END c13[5]
  PIN c13[6]
    DIRECTION OUTPUT TRISTATE ;
    USE SIGNAL ;
    ANTENNADIFFAREA 0.795200 ;
    PORT
      LAYER met2 ;
        RECT 351.070 0.000 351.350 4.000 ;
    END
  END c13[6]
  PIN c13[7]
    DIRECTION OUTPUT TRISTATE ;
    USE SIGNAL ;
    ANTENNADIFFAREA 0.795200 ;
    PORT
      LAYER met2 ;
        RECT 164.310 0.000 164.590 4.000 ;
    END
  END c13[7]
  PIN c13[8]
    DIRECTION OUTPUT TRISTATE ;
    USE SIGNAL ;
    ANTENNADIFFAREA 0.795200 ;
    PORT
      LAYER met2 ;
        RECT 331.750 0.000 332.030 4.000 ;
    END
  END c13[8]
  PIN c13[9]
    DIRECTION OUTPUT TRISTATE ;
    USE SIGNAL ;
    ANTENNADIFFAREA 0.795200 ;
    PORT
      LAYER met3 ;
        RECT 519.720 149.640 523.720 150.240 ;
    END
  END c13[9]
  PIN c20[0]
    DIRECTION OUTPUT TRISTATE ;
    USE SIGNAL ;
    ANTENNADIFFAREA 0.445500 ;
    PORT
      LAYER met3 ;
        RECT 519.720 238.040 523.720 238.640 ;
    END
  END c20[0]
  PIN c20[10]
    DIRECTION OUTPUT TRISTATE ;
    USE SIGNAL ;
    ANTENNADIFFAREA 0.795200 ;
    PORT
      LAYER met2 ;
        RECT 48.390 530.440 48.670 534.440 ;
    END
  END c20[10]
  PIN c20[11]
    DIRECTION OUTPUT TRISTATE ;
    USE SIGNAL ;
    ANTENNADIFFAREA 0.795200 ;
    PORT
      LAYER met3 ;
        RECT 0.000 51.040 4.000 51.640 ;
    END
  END c20[11]
  PIN c20[12]
    DIRECTION OUTPUT TRISTATE ;
    USE SIGNAL ;
    ANTENNADIFFAREA 0.795200 ;
    PORT
      LAYER met2 ;
        RECT 441.230 0.000 441.510 4.000 ;
    END
  END c20[12]
  PIN c20[13]
    DIRECTION OUTPUT TRISTATE ;
    USE SIGNAL ;
    ANTENNADIFFAREA 0.445500 ;
    PORT
      LAYER met3 ;
        RECT 519.720 224.440 523.720 225.040 ;
    END
  END c20[13]
  PIN c20[14]
    DIRECTION OUTPUT TRISTATE ;
    USE SIGNAL ;
    ANTENNADIFFAREA 0.795200 ;
    PORT
      LAYER met2 ;
        RECT 505.630 530.440 505.910 534.440 ;
    END
  END c20[14]
  PIN c20[15]
    DIRECTION OUTPUT TRISTATE ;
    USE SIGNAL ;
    ANTENNADIFFAREA 0.795200 ;
    PORT
      LAYER met2 ;
        RECT 235.150 530.440 235.430 534.440 ;
    END
  END c20[15]
  PIN c20[1]
    DIRECTION OUTPUT TRISTATE ;
    USE SIGNAL ;
    ANTENNADIFFAREA 0.795200 ;
    PORT
      LAYER met2 ;
        RECT 344.630 0.000 344.910 4.000 ;
    END
  END c20[1]
  PIN c20[2]
    DIRECTION OUTPUT TRISTATE ;
    USE SIGNAL ;
    ANTENNADIFFAREA 0.795200 ;
    PORT
      LAYER met3 ;
        RECT 519.720 462.440 523.720 463.040 ;
    END
  END c20[2]
  PIN c20[3]
    DIRECTION OUTPUT TRISTATE ;
    USE SIGNAL ;
    ANTENNADIFFAREA 0.795200 ;
    PORT
      LAYER met2 ;
        RECT 499.190 0.000 499.470 4.000 ;
    END
  END c20[3]
  PIN c20[4]
    DIRECTION OUTPUT TRISTATE ;
    USE SIGNAL ;
    ANTENNADIFFAREA 0.795200 ;
    PORT
      LAYER met2 ;
        RECT 460.550 530.440 460.830 534.440 ;
    END
  END c20[4]
  PIN c20[5]
    DIRECTION OUTPUT TRISTATE ;
    USE SIGNAL ;
    ANTENNADIFFAREA 0.795200 ;
    PORT
      LAYER met2 ;
        RECT 421.910 0.000 422.190 4.000 ;
    END
  END c20[5]
  PIN c20[6]
    DIRECTION OUTPUT TRISTATE ;
    USE SIGNAL ;
    ANTENNADIFFAREA 0.795200 ;
    PORT
      LAYER met3 ;
        RECT 0.000 132.640 4.000 133.240 ;
    END
  END c20[6]
  PIN c20[7]
    DIRECTION OUTPUT TRISTATE ;
    USE SIGNAL ;
    ANTENNADIFFAREA 0.795200 ;
    PORT
      LAYER met2 ;
        RECT 54.830 0.000 55.110 4.000 ;
    END
  END c20[7]
  PIN c20[8]
    DIRECTION OUTPUT TRISTATE ;
    USE SIGNAL ;
    ANTENNADIFFAREA 0.795200 ;
    PORT
      LAYER met3 ;
        RECT 0.000 533.840 4.000 534.440 ;
    END
  END c20[8]
  PIN c20[9]
    DIRECTION OUTPUT TRISTATE ;
    USE SIGNAL ;
    ANTENNADIFFAREA 0.795200 ;
    PORT
      LAYER met2 ;
        RECT 254.470 0.000 254.750 4.000 ;
    END
  END c20[9]
  PIN c21[0]
    DIRECTION OUTPUT TRISTATE ;
    USE SIGNAL ;
    ANTENNADIFFAREA 0.445500 ;
    PORT
      LAYER met3 ;
        RECT 519.720 251.640 523.720 252.240 ;
    END
  END c21[0]
  PIN c21[10]
    DIRECTION OUTPUT TRISTATE ;
    USE SIGNAL ;
    ANTENNADIFFAREA 0.795200 ;
    PORT
      LAYER met3 ;
        RECT 0.000 85.040 4.000 85.640 ;
    END
  END c21[10]
  PIN c21[11]
    DIRECTION OUTPUT TRISTATE ;
    USE SIGNAL ;
    ANTENNADIFFAREA 0.795200 ;
    PORT
      LAYER met2 ;
        RECT 434.790 0.000 435.070 4.000 ;
    END
  END c21[11]
  PIN c21[12]
    DIRECTION OUTPUT TRISTATE ;
    USE SIGNAL ;
    ANTENNADIFFAREA 0.445500 ;
    PORT
      LAYER met2 ;
        RECT 305.990 530.440 306.270 534.440 ;
    END
  END c21[12]
  PIN c21[13]
    DIRECTION OUTPUT TRISTATE ;
    USE SIGNAL ;
    ANTENNADIFFAREA 0.795200 ;
    PORT
      LAYER met3 ;
        RECT 519.720 489.640 523.720 490.240 ;
    END
  END c21[13]
  PIN c21[14]
    DIRECTION OUTPUT TRISTATE ;
    USE SIGNAL ;
    ANTENNADIFFAREA 0.795200 ;
    PORT
      LAYER met2 ;
        RECT 119.230 530.440 119.510 534.440 ;
    END
  END c21[14]
  PIN c21[15]
    DIRECTION OUTPUT TRISTATE ;
    USE SIGNAL ;
    ANTENNADIFFAREA 0.795200 ;
    PORT
      LAYER met2 ;
        RECT 29.070 530.440 29.350 534.440 ;
    END
  END c21[15]
  PIN c21[1]
    DIRECTION OUTPUT TRISTATE ;
    USE SIGNAL ;
    ANTENNADIFFAREA 0.795200 ;
    PORT
      LAYER met2 ;
        RECT 318.870 530.440 319.150 534.440 ;
    END
  END c21[1]
  PIN c21[2]
    DIRECTION OUTPUT TRISTATE ;
    USE SIGNAL ;
    ANTENNADIFFAREA 0.795200 ;
    PORT
      LAYER met3 ;
        RECT 519.720 20.440 523.720 21.040 ;
    END
  END c21[2]
  PIN c21[3]
    DIRECTION OUTPUT TRISTATE ;
    USE SIGNAL ;
    ANTENNADIFFAREA 0.795200 ;
    PORT
      LAYER met2 ;
        RECT 248.030 530.440 248.310 534.440 ;
    END
  END c21[3]
  PIN c21[4]
    DIRECTION OUTPUT TRISTATE ;
    USE SIGNAL ;
    ANTENNADIFFAREA 0.445500 ;
    PORT
      LAYER met3 ;
        RECT 519.720 108.840 523.720 109.440 ;
    END
  END c21[4]
  PIN c21[5]
    DIRECTION OUTPUT TRISTATE ;
    USE SIGNAL ;
    ANTENNADIFFAREA 0.795200 ;
    PORT
      LAYER met2 ;
        RECT 466.990 530.440 467.270 534.440 ;
    END
  END c21[5]
  PIN c21[6]
    DIRECTION OUTPUT TRISTATE ;
    USE SIGNAL ;
    ANTENNADIFFAREA 0.795200 ;
    PORT
      LAYER met2 ;
        RECT 363.950 530.440 364.230 534.440 ;
    END
  END c21[6]
  PIN c21[7]
    DIRECTION OUTPUT TRISTATE ;
    USE SIGNAL ;
    ANTENNADIFFAREA 0.795200 ;
    PORT
      LAYER met3 ;
        RECT 0.000 159.840 4.000 160.440 ;
    END
  END c21[7]
  PIN c21[8]
    DIRECTION OUTPUT TRISTATE ;
    USE SIGNAL ;
    ANTENNADIFFAREA 0.795200 ;
    PORT
      LAYER met3 ;
        RECT 0.000 255.040 4.000 255.640 ;
    END
  END c21[8]
  PIN c21[9]
    DIRECTION OUTPUT TRISTATE ;
    USE SIGNAL ;
    ANTENNADIFFAREA 0.795200 ;
    PORT
      LAYER met2 ;
        RECT 41.950 530.440 42.230 534.440 ;
    END
  END c21[9]
  PIN c22[0]
    DIRECTION OUTPUT TRISTATE ;
    USE SIGNAL ;
    ANTENNADIFFAREA 0.445500 ;
    PORT
      LAYER met3 ;
        RECT 519.720 306.040 523.720 306.640 ;
    END
  END c22[0]
  PIN c22[10]
    DIRECTION OUTPUT TRISTATE ;
    USE SIGNAL ;
    ANTENNADIFFAREA 0.795200 ;
    PORT
      LAYER met3 ;
        RECT 0.000 391.040 4.000 391.640 ;
    END
  END c22[10]
  PIN c22[11]
    DIRECTION OUTPUT TRISTATE ;
    USE SIGNAL ;
    ANTENNADIFFAREA 0.795200 ;
    PORT
      LAYER met2 ;
        RECT 299.550 0.000 299.830 4.000 ;
    END
  END c22[11]
  PIN c22[12]
    DIRECTION OUTPUT TRISTATE ;
    USE SIGNAL ;
    ANTENNADIFFAREA 0.795200 ;
    PORT
      LAYER met2 ;
        RECT 22.630 530.440 22.910 534.440 ;
    END
  END c22[12]
  PIN c22[13]
    DIRECTION OUTPUT TRISTATE ;
    USE SIGNAL ;
    ANTENNADIFFAREA 0.795200 ;
    PORT
      LAYER met3 ;
        RECT 519.720 102.040 523.720 102.640 ;
    END
  END c22[13]
  PIN c22[14]
    DIRECTION OUTPUT TRISTATE ;
    USE SIGNAL ;
    ANTENNADIFFAREA 0.795200 ;
    PORT
      LAYER met2 ;
        RECT 454.110 0.000 454.390 4.000 ;
    END
  END c22[14]
  PIN c22[15]
    DIRECTION OUTPUT TRISTATE ;
    USE SIGNAL ;
    ANTENNADIFFAREA 0.795200 ;
    PORT
      LAYER met2 ;
        RECT 441.230 530.440 441.510 534.440 ;
    END
  END c22[15]
  PIN c22[1]
    DIRECTION OUTPUT TRISTATE ;
    USE SIGNAL ;
    ANTENNADIFFAREA 0.795200 ;
    PORT
      LAYER met3 ;
        RECT 519.720 482.840 523.720 483.440 ;
    END
  END c22[1]
  PIN c22[2]
    DIRECTION OUTPUT TRISTATE ;
    USE SIGNAL ;
    ANTENNADIFFAREA 0.795200 ;
    PORT
      LAYER met2 ;
        RECT 267.350 0.000 267.630 4.000 ;
    END
  END c22[2]
  PIN c22[3]
    DIRECTION OUTPUT TRISTATE ;
    USE SIGNAL ;
    ANTENNADIFFAREA 0.795200 ;
    PORT
      LAYER met2 ;
        RECT 383.270 0.000 383.550 4.000 ;
    END
  END c22[3]
  PIN c22[4]
    DIRECTION OUTPUT TRISTATE ;
    USE SIGNAL ;
    ANTENNADIFFAREA 0.795200 ;
    PORT
      LAYER met3 ;
        RECT 519.720 61.240 523.720 61.840 ;
    END
  END c22[4]
  PIN c22[5]
    DIRECTION OUTPUT TRISTATE ;
    USE SIGNAL ;
    ANTENNADIFFAREA 0.795200 ;
    PORT
      LAYER met2 ;
        RECT 183.630 530.440 183.910 534.440 ;
    END
  END c22[5]
  PIN c22[6]
    DIRECTION OUTPUT TRISTATE ;
    USE SIGNAL ;
    ANTENNADIFFAREA 0.795200 ;
    PORT
      LAYER met2 ;
        RECT 260.910 0.000 261.190 4.000 ;
    END
  END c22[6]
  PIN c22[7]
    DIRECTION OUTPUT TRISTATE ;
    USE SIGNAL ;
    ANTENNADIFFAREA 0.795200 ;
    PORT
      LAYER met2 ;
        RECT 48.390 0.000 48.670 4.000 ;
    END
  END c22[7]
  PIN c22[8]
    DIRECTION OUTPUT TRISTATE ;
    USE SIGNAL ;
    ANTENNADIFFAREA 0.795200 ;
    PORT
      LAYER met2 ;
        RECT 280.230 530.440 280.510 534.440 ;
    END
  END c22[8]
  PIN c22[9]
    DIRECTION OUTPUT TRISTATE ;
    USE SIGNAL ;
    ANTENNADIFFAREA 0.445500 ;
    PORT
      LAYER met3 ;
        RECT 519.720 244.840 523.720 245.440 ;
    END
  END c22[9]
  PIN c23[0]
    DIRECTION OUTPUT TRISTATE ;
    USE SIGNAL ;
    ANTENNADIFFAREA 0.445500 ;
    PORT
      LAYER met3 ;
        RECT 519.720 442.040 523.720 442.640 ;
    END
  END c23[0]
  PIN c23[10]
    DIRECTION OUTPUT TRISTATE ;
    USE SIGNAL ;
    ANTENNADIFFAREA 0.795200 ;
    PORT
      LAYER met2 ;
        RECT 183.630 0.000 183.910 4.000 ;
    END
  END c23[10]
  PIN c23[11]
    DIRECTION OUTPUT TRISTATE ;
    USE SIGNAL ;
    ANTENNADIFFAREA 0.795200 ;
    PORT
      LAYER met2 ;
        RECT 492.750 530.440 493.030 534.440 ;
    END
  END c23[11]
  PIN c23[12]
    DIRECTION OUTPUT TRISTATE ;
    USE SIGNAL ;
    ANTENNADIFFAREA 0.795200 ;
    PORT
      LAYER met3 ;
        RECT 519.720 170.040 523.720 170.640 ;
    END
  END c23[12]
  PIN c23[13]
    DIRECTION OUTPUT TRISTATE ;
    USE SIGNAL ;
    ANTENNADIFFAREA 0.795200 ;
    PORT
      LAYER met2 ;
        RECT 376.830 0.000 377.110 4.000 ;
    END
  END c23[13]
  PIN c23[14]
    DIRECTION OUTPUT TRISTATE ;
    USE SIGNAL ;
    ANTENNADIFFAREA 0.795200 ;
    PORT
      LAYER met2 ;
        RECT 479.870 530.440 480.150 534.440 ;
    END
  END c23[14]
  PIN c23[15]
    DIRECTION OUTPUT TRISTATE ;
    USE SIGNAL ;
    ANTENNADIFFAREA 0.795200 ;
    PORT
      LAYER met2 ;
        RECT 363.950 0.000 364.230 4.000 ;
    END
  END c23[15]
  PIN c23[1]
    DIRECTION OUTPUT TRISTATE ;
    USE SIGNAL ;
    ANTENNADIFFAREA 0.795200 ;
    PORT
      LAYER met3 ;
        RECT 0.000 336.640 4.000 337.240 ;
    END
  END c23[1]
  PIN c23[2]
    DIRECTION OUTPUT TRISTATE ;
    USE SIGNAL ;
    ANTENNADIFFAREA 0.795200 ;
    PORT
      LAYER met3 ;
        RECT 0.000 445.440 4.000 446.040 ;
    END
  END c23[2]
  PIN c23[3]
    DIRECTION OUTPUT TRISTATE ;
    USE SIGNAL ;
    ANTENNADIFFAREA 0.795200 ;
    PORT
      LAYER met2 ;
        RECT 486.310 0.000 486.590 4.000 ;
    END
  END c23[3]
  PIN c23[4]
    DIRECTION OUTPUT TRISTATE ;
    USE SIGNAL ;
    ANTENNADIFFAREA 0.795200 ;
    PORT
      LAYER met3 ;
        RECT 519.720 95.240 523.720 95.840 ;
    END
  END c23[4]
  PIN c23[5]
    DIRECTION OUTPUT TRISTATE ;
    USE SIGNAL ;
    ANTENNADIFFAREA 0.795200 ;
    PORT
      LAYER met2 ;
        RECT 254.470 530.440 254.750 534.440 ;
    END
  END c23[5]
  PIN c23[6]
    DIRECTION OUTPUT TRISTATE ;
    USE SIGNAL ;
    ANTENNADIFFAREA 0.795200 ;
    PORT
      LAYER met3 ;
        RECT 519.720 408.040 523.720 408.640 ;
    END
  END c23[6]
  PIN c23[7]
    DIRECTION OUTPUT TRISTATE ;
    USE SIGNAL ;
    ANTENNADIFFAREA 0.795200 ;
    PORT
      LAYER met3 ;
        RECT 0.000 520.240 4.000 520.840 ;
    END
  END c23[7]
  PIN c23[8]
    DIRECTION OUTPUT TRISTATE ;
    USE SIGNAL ;
    ANTENNADIFFAREA 0.795200 ;
    PORT
      LAYER met2 ;
        RECT 16.190 530.440 16.470 534.440 ;
    END
  END c23[8]
  PIN c23[9]
    DIRECTION OUTPUT TRISTATE ;
    USE SIGNAL ;
    ANTENNADIFFAREA 0.795200 ;
    PORT
      LAYER met2 ;
        RECT 3.310 530.440 3.590 534.440 ;
    END
  END c23[9]
  PIN c30[0]
    DIRECTION OUTPUT TRISTATE ;
    USE SIGNAL ;
    ANTENNADIFFAREA 0.795200 ;
    PORT
      LAYER met2 ;
        RECT 16.190 0.000 16.470 4.000 ;
    END
  END c30[0]
  PIN c30[10]
    DIRECTION OUTPUT TRISTATE ;
    USE SIGNAL ;
    ANTENNADIFFAREA 0.795200 ;
    PORT
      LAYER met3 ;
        RECT 0.000 146.240 4.000 146.840 ;
    END
  END c30[10]
  PIN c30[11]
    DIRECTION OUTPUT TRISTATE ;
    USE SIGNAL ;
    ANTENNADIFFAREA 0.445500 ;
    PORT
      LAYER met3 ;
        RECT 519.720 231.240 523.720 231.840 ;
    END
  END c30[11]
  PIN c30[12]
    DIRECTION OUTPUT TRISTATE ;
    USE SIGNAL ;
    ANTENNADIFFAREA 0.795200 ;
    PORT
      LAYER met2 ;
        RECT 280.230 0.000 280.510 4.000 ;
    END
  END c30[12]
  PIN c30[13]
    DIRECTION OUTPUT TRISTATE ;
    USE SIGNAL ;
    ANTENNADIFFAREA 0.795200 ;
    PORT
      LAYER met2 ;
        RECT 421.910 530.440 422.190 534.440 ;
    END
  END c30[13]
  PIN c30[14]
    DIRECTION OUTPUT TRISTATE ;
    USE SIGNAL ;
    ANTENNADIFFAREA 0.795200 ;
    PORT
      LAYER met3 ;
        RECT 519.720 523.640 523.720 524.240 ;
    END
  END c30[14]
  PIN c30[15]
    DIRECTION OUTPUT TRISTATE ;
    USE SIGNAL ;
    ANTENNADIFFAREA 0.795200 ;
    PORT
      LAYER met2 ;
        RECT 106.350 530.440 106.630 534.440 ;
    END
  END c30[15]
  PIN c30[1]
    DIRECTION OUTPUT TRISTATE ;
    USE SIGNAL ;
    ANTENNADIFFAREA 0.795200 ;
    PORT
      LAYER met2 ;
        RECT 74.150 0.000 74.430 4.000 ;
    END
  END c30[1]
  PIN c30[2]
    DIRECTION OUTPUT TRISTATE ;
    USE SIGNAL ;
    ANTENNADIFFAREA 0.795200 ;
    PORT
      LAYER met3 ;
        RECT 0.000 248.240 4.000 248.840 ;
    END
  END c30[2]
  PIN c30[3]
    DIRECTION OUTPUT TRISTATE ;
    USE SIGNAL ;
    ANTENNADIFFAREA 0.795200 ;
    PORT
      LAYER met3 ;
        RECT 519.720 510.040 523.720 510.640 ;
    END
  END c30[3]
  PIN c30[4]
    DIRECTION OUTPUT TRISTATE ;
    USE SIGNAL ;
    ANTENNADIFFAREA 0.795200 ;
    PORT
      LAYER met3 ;
        RECT 0.000 404.640 4.000 405.240 ;
    END
  END c30[4]
  PIN c30[5]
    DIRECTION OUTPUT TRISTATE ;
    USE SIGNAL ;
    ANTENNADIFFAREA 0.445500 ;
    PORT
      LAYER met3 ;
        RECT 519.720 374.040 523.720 374.640 ;
    END
  END c30[5]
  PIN c30[6]
    DIRECTION OUTPUT TRISTATE ;
    USE SIGNAL ;
    ANTENNADIFFAREA 0.795200 ;
    PORT
      LAYER met3 ;
        RECT 0.000 105.440 4.000 106.040 ;
    END
  END c30[6]
  PIN c30[7]
    DIRECTION OUTPUT TRISTATE ;
    USE SIGNAL ;
    ANTENNADIFFAREA 0.795200 ;
    PORT
      LAYER met3 ;
        RECT 0.000 207.440 4.000 208.040 ;
    END
  END c30[7]
  PIN c30[8]
    DIRECTION OUTPUT TRISTATE ;
    USE SIGNAL ;
    ANTENNADIFFAREA 0.795200 ;
    PORT
      LAYER met2 ;
        RECT 486.310 530.440 486.590 534.440 ;
    END
  END c30[8]
  PIN c30[9]
    DIRECTION OUTPUT TRISTATE ;
    USE SIGNAL ;
    ANTENNADIFFAREA 0.795200 ;
    PORT
      LAYER met2 ;
        RECT 190.070 530.440 190.350 534.440 ;
    END
  END c30[9]
  PIN c31[0]
    DIRECTION OUTPUT TRISTATE ;
    USE SIGNAL ;
    ANTENNADIFFAREA 0.795200 ;
    PORT
      LAYER met2 ;
        RECT 151.430 0.000 151.710 4.000 ;
    END
  END c31[0]
  PIN c31[10]
    DIRECTION OUTPUT TRISTATE ;
    USE SIGNAL ;
    ANTENNADIFFAREA 0.445500 ;
    PORT
      LAYER met3 ;
        RECT 519.720 285.640 523.720 286.240 ;
    END
  END c31[10]
  PIN c31[11]
    DIRECTION OUTPUT TRISTATE ;
    USE SIGNAL ;
    ANTENNADIFFAREA 0.795200 ;
    PORT
      LAYER met2 ;
        RECT 409.030 0.000 409.310 4.000 ;
    END
  END c31[11]
  PIN c31[12]
    DIRECTION OUTPUT TRISTATE ;
    USE SIGNAL ;
    ANTENNADIFFAREA 0.795200 ;
    PORT
      LAYER met3 ;
        RECT 519.720 129.240 523.720 129.840 ;
    END
  END c31[12]
  PIN c31[13]
    DIRECTION OUTPUT TRISTATE ;
    USE SIGNAL ;
    ANTENNADIFFAREA 0.795200 ;
    PORT
      LAYER met3 ;
        RECT 0.000 357.040 4.000 357.640 ;
    END
  END c31[13]
  PIN c31[14]
    DIRECTION OUTPUT TRISTATE ;
    USE SIGNAL ;
    ANTENNADIFFAREA 0.795200 ;
    PORT
      LAYER met2 ;
        RECT 518.510 0.000 518.790 4.000 ;
    END
  END c31[14]
  PIN c31[15]
    DIRECTION OUTPUT TRISTATE ;
    USE SIGNAL ;
    ANTENNADIFFAREA 0.795200 ;
    PORT
      LAYER met2 ;
        RECT 80.590 0.000 80.870 4.000 ;
    END
  END c31[15]
  PIN c31[1]
    DIRECTION OUTPUT TRISTATE ;
    USE SIGNAL ;
    ANTENNADIFFAREA 0.795200 ;
    PORT
      LAYER met2 ;
        RECT 248.030 0.000 248.310 4.000 ;
    END
  END c31[1]
  PIN c31[2]
    DIRECTION OUTPUT TRISTATE ;
    USE SIGNAL ;
    ANTENNADIFFAREA 0.445500 ;
    PORT
      LAYER met3 ;
        RECT 519.720 204.040 523.720 204.640 ;
    END
  END c31[2]
  PIN c31[3]
    DIRECTION OUTPUT TRISTATE ;
    USE SIGNAL ;
    ANTENNADIFFAREA 0.795200 ;
    PORT
      LAYER met2 ;
        RECT 454.110 530.440 454.390 534.440 ;
    END
  END c31[3]
  PIN c31[4]
    DIRECTION OUTPUT TRISTATE ;
    USE SIGNAL ;
    ANTENNADIFFAREA 0.445500 ;
    PORT
      LAYER met3 ;
        RECT 519.720 448.840 523.720 449.440 ;
    END
  END c31[4]
  PIN c31[5]
    DIRECTION OUTPUT TRISTATE ;
    USE SIGNAL ;
    ANTENNADIFFAREA 0.795200 ;
    PORT
      LAYER met3 ;
        RECT 519.720 0.040 523.720 0.640 ;
    END
  END c31[5]
  PIN c31[6]
    DIRECTION OUTPUT TRISTATE ;
    USE SIGNAL ;
    ANTENNADIFFAREA 0.795200 ;
    PORT
      LAYER met3 ;
        RECT 0.000 139.440 4.000 140.040 ;
    END
  END c31[6]
  PIN c31[7]
    DIRECTION OUTPUT TRISTATE ;
    USE SIGNAL ;
    ANTENNADIFFAREA 0.445500 ;
    PORT
      LAYER met3 ;
        RECT 519.720 278.840 523.720 279.440 ;
    END
  END c31[7]
  PIN c31[8]
    DIRECTION OUTPUT TRISTATE ;
    USE SIGNAL ;
    ANTENNADIFFAREA 0.795200 ;
    PORT
      LAYER met2 ;
        RECT 9.750 0.000 10.030 4.000 ;
    END
  END c31[8]
  PIN c31[9]
    DIRECTION OUTPUT TRISTATE ;
    USE SIGNAL ;
    ANTENNADIFFAREA 0.445500 ;
    PORT
      LAYER met3 ;
        RECT 519.720 469.240 523.720 469.840 ;
    END
  END c31[9]
  PIN c32[0]
    DIRECTION OUTPUT TRISTATE ;
    USE SIGNAL ;
    ANTENNADIFFAREA 0.795200 ;
    PORT
      LAYER met2 ;
        RECT 428.350 530.440 428.630 534.440 ;
    END
  END c32[0]
  PIN c32[10]
    DIRECTION OUTPUT TRISTATE ;
    USE SIGNAL ;
    ANTENNADIFFAREA 0.795200 ;
    PORT
      LAYER met3 ;
        RECT 519.720 40.840 523.720 41.440 ;
    END
  END c32[10]
  PIN c32[11]
    DIRECTION OUTPUT TRISTATE ;
    USE SIGNAL ;
    ANTENNADIFFAREA 0.795200 ;
    PORT
      LAYER met2 ;
        RECT 409.030 530.440 409.310 534.440 ;
    END
  END c32[11]
  PIN c32[12]
    DIRECTION OUTPUT TRISTATE ;
    USE SIGNAL ;
    ANTENNADIFFAREA 0.795200 ;
    PORT
      LAYER met3 ;
        RECT 0.000 193.840 4.000 194.440 ;
    END
  END c32[12]
  PIN c32[13]
    DIRECTION OUTPUT TRISTATE ;
    USE SIGNAL ;
    ANTENNADIFFAREA 0.795200 ;
    PORT
      LAYER met3 ;
        RECT 0.000 153.040 4.000 153.640 ;
    END
  END c32[13]
  PIN c32[14]
    DIRECTION OUTPUT TRISTATE ;
    USE SIGNAL ;
    ANTENNADIFFAREA 0.795200 ;
    PORT
      LAYER met2 ;
        RECT 338.190 0.000 338.470 4.000 ;
    END
  END c32[14]
  PIN c32[15]
    DIRECTION OUTPUT TRISTATE ;
    USE SIGNAL ;
    ANTENNADIFFAREA 0.795200 ;
    PORT
      LAYER met2 ;
        RECT 0.090 0.000 0.370 4.000 ;
    END
  END c32[15]
  PIN c32[1]
    DIRECTION OUTPUT TRISTATE ;
    USE SIGNAL ;
    ANTENNADIFFAREA 0.795200 ;
    PORT
      LAYER met2 ;
        RECT 396.150 0.000 396.430 4.000 ;
    END
  END c32[1]
  PIN c32[2]
    DIRECTION OUTPUT TRISTATE ;
    USE SIGNAL ;
    ANTENNADIFFAREA 0.795200 ;
    PORT
      LAYER met3 ;
        RECT 0.000 295.840 4.000 296.440 ;
    END
  END c32[2]
  PIN c32[3]
    DIRECTION OUTPUT TRISTATE ;
    USE SIGNAL ;
    ANTENNADIFFAREA 0.795200 ;
    PORT
      LAYER met3 ;
        RECT 0.000 499.840 4.000 500.440 ;
    END
  END c32[3]
  PIN c32[4]
    DIRECTION OUTPUT TRISTATE ;
    USE SIGNAL ;
    ANTENNADIFFAREA 0.795200 ;
    PORT
      LAYER met3 ;
        RECT 0.000 125.840 4.000 126.440 ;
    END
  END c32[4]
  PIN c32[5]
    DIRECTION OUTPUT TRISTATE ;
    USE SIGNAL ;
    ANTENNADIFFAREA 0.795200 ;
    PORT
      LAYER met3 ;
        RECT 0.000 214.240 4.000 214.840 ;
    END
  END c32[5]
  PIN c32[6]
    DIRECTION OUTPUT TRISTATE ;
    USE SIGNAL ;
    ANTENNADIFFAREA 0.795200 ;
    PORT
      LAYER met2 ;
        RECT 99.910 0.000 100.190 4.000 ;
    END
  END c32[6]
  PIN c32[7]
    DIRECTION OUTPUT TRISTATE ;
    USE SIGNAL ;
    ANTENNADIFFAREA 0.795200 ;
    PORT
      LAYER met2 ;
        RECT 35.510 0.000 35.790 4.000 ;
    END
  END c32[7]
  PIN c32[8]
    DIRECTION OUTPUT TRISTATE ;
    USE SIGNAL ;
    ANTENNADIFFAREA 0.795200 ;
    PORT
      LAYER met2 ;
        RECT 293.110 530.440 293.390 534.440 ;
    END
  END c32[8]
  PIN c32[9]
    DIRECTION OUTPUT TRISTATE ;
    USE SIGNAL ;
    ANTENNADIFFAREA 0.795200 ;
    PORT
      LAYER met2 ;
        RECT 177.190 530.440 177.470 534.440 ;
    END
  END c32[9]
  PIN c33[0]
    DIRECTION OUTPUT TRISTATE ;
    USE SIGNAL ;
    ANTENNADIFFAREA 0.795200 ;
    PORT
      LAYER met2 ;
        RECT 273.790 0.000 274.070 4.000 ;
    END
  END c33[0]
  PIN c33[10]
    DIRECTION OUTPUT TRISTATE ;
    USE SIGNAL ;
    ANTENNADIFFAREA 0.795200 ;
    PORT
      LAYER met2 ;
        RECT 383.270 530.440 383.550 534.440 ;
    END
  END c33[10]
  PIN c33[11]
    DIRECTION OUTPUT TRISTATE ;
    USE SIGNAL ;
    ANTENNADIFFAREA 0.445500 ;
    PORT
      LAYER met3 ;
        RECT 519.720 136.040 523.720 136.640 ;
    END
  END c33[11]
  PIN c33[12]
    DIRECTION OUTPUT TRISTATE ;
    USE SIGNAL ;
    ANTENNADIFFAREA 0.795200 ;
    PORT
      LAYER met3 ;
        RECT 0.000 377.440 4.000 378.040 ;
    END
  END c33[12]
  PIN c33[13]
    DIRECTION OUTPUT TRISTATE ;
    USE SIGNAL ;
    ANTENNADIFFAREA 0.445500 ;
    PORT
      LAYER met3 ;
        RECT 519.720 401.240 523.720 401.840 ;
    END
  END c33[13]
  PIN c33[14]
    DIRECTION OUTPUT TRISTATE ;
    USE SIGNAL ;
    ANTENNADIFFAREA 0.795200 ;
    PORT
      LAYER met2 ;
        RECT 112.790 0.000 113.070 4.000 ;
    END
  END c33[14]
  PIN c33[15]
    DIRECTION OUTPUT TRISTATE ;
    USE SIGNAL ;
    ANTENNADIFFAREA 0.795200 ;
    PORT
      LAYER met2 ;
        RECT 196.510 0.000 196.790 4.000 ;
    END
  END c33[15]
  PIN c33[1]
    DIRECTION OUTPUT TRISTATE ;
    USE SIGNAL ;
    ANTENNADIFFAREA 0.795200 ;
    PORT
      LAYER met3 ;
        RECT 0.000 57.840 4.000 58.440 ;
    END
  END c33[1]
  PIN c33[2]
    DIRECTION OUTPUT TRISTATE ;
    USE SIGNAL ;
    ANTENNADIFFAREA 0.445500 ;
    PORT
      LAYER met3 ;
        RECT 519.720 387.640 523.720 388.240 ;
    END
  END c33[2]
  PIN c33[3]
    DIRECTION OUTPUT TRISTATE ;
    USE SIGNAL ;
    ANTENNADIFFAREA 0.795200 ;
    PORT
      LAYER met2 ;
        RECT 305.990 0.000 306.270 4.000 ;
    END
  END c33[3]
  PIN c33[4]
    DIRECTION OUTPUT TRISTATE ;
    USE SIGNAL ;
    ANTENNADIFFAREA 0.795200 ;
    PORT
      LAYER met2 ;
        RECT 351.070 530.440 351.350 534.440 ;
    END
  END c33[4]
  PIN c33[5]
    DIRECTION OUTPUT TRISTATE ;
    USE SIGNAL ;
    ANTENNADIFFAREA 0.795200 ;
    PORT
      LAYER met2 ;
        RECT 344.630 530.440 344.910 534.440 ;
    END
  END c33[5]
  PIN c33[6]
    DIRECTION OUTPUT TRISTATE ;
    USE SIGNAL ;
    ANTENNADIFFAREA 0.795200 ;
    PORT
      LAYER met3 ;
        RECT 0.000 506.640 4.000 507.240 ;
    END
  END c33[6]
  PIN c33[7]
    DIRECTION OUTPUT TRISTATE ;
    USE SIGNAL ;
    ANTENNADIFFAREA 0.795200 ;
    PORT
      LAYER met2 ;
        RECT 67.710 530.440 67.990 534.440 ;
    END
  END c33[7]
  PIN c33[8]
    DIRECTION OUTPUT TRISTATE ;
    USE SIGNAL ;
    ANTENNADIFFAREA 0.795200 ;
    PORT
      LAYER met2 ;
        RECT 370.390 0.000 370.670 4.000 ;
    END
  END c33[8]
  PIN c33[9]
    DIRECTION OUTPUT TRISTATE ;
    USE SIGNAL ;
    ANTENNADIFFAREA 0.795200 ;
    PORT
      LAYER met3 ;
        RECT 0.000 119.040 4.000 119.640 ;
    END
  END c33[9]
  PIN clk
    DIRECTION INPUT ;
    USE SIGNAL ;
    ANTENNAGATEAREA 0.852000 ;
    PORT
      LAYER met3 ;
        RECT 0.000 452.240 4.000 452.840 ;
    END
  END clk
  PIN reset
    DIRECTION INPUT ;
    USE SIGNAL ;
    ANTENNAGATEAREA 0.213000 ;
    PORT
      LAYER met3 ;
        RECT 519.720 258.440 523.720 259.040 ;
    END
  END reset
  OBS
      LAYER li1 ;
        RECT 5.520 10.795 517.960 522.325 ;
      LAYER met1 ;
        RECT 0.070 8.540 522.030 524.240 ;
      LAYER met2 ;
        RECT 0.100 530.160 3.030 534.325 ;
        RECT 3.870 530.160 9.470 534.325 ;
        RECT 10.310 530.160 15.910 534.325 ;
        RECT 16.750 530.160 22.350 534.325 ;
        RECT 23.190 530.160 28.790 534.325 ;
        RECT 29.630 530.160 35.230 534.325 ;
        RECT 36.070 530.160 41.670 534.325 ;
        RECT 42.510 530.160 48.110 534.325 ;
        RECT 48.950 530.160 54.550 534.325 ;
        RECT 55.390 530.160 60.990 534.325 ;
        RECT 61.830 530.160 67.430 534.325 ;
        RECT 68.270 530.160 73.870 534.325 ;
        RECT 74.710 530.160 80.310 534.325 ;
        RECT 81.150 530.160 86.750 534.325 ;
        RECT 87.590 530.160 93.190 534.325 ;
        RECT 94.030 530.160 99.630 534.325 ;
        RECT 100.470 530.160 106.070 534.325 ;
        RECT 106.910 530.160 112.510 534.325 ;
        RECT 113.350 530.160 118.950 534.325 ;
        RECT 119.790 530.160 125.390 534.325 ;
        RECT 126.230 530.160 131.830 534.325 ;
        RECT 132.670 530.160 138.270 534.325 ;
        RECT 139.110 530.160 144.710 534.325 ;
        RECT 145.550 530.160 151.150 534.325 ;
        RECT 151.990 530.160 157.590 534.325 ;
        RECT 158.430 530.160 164.030 534.325 ;
        RECT 164.870 530.160 170.470 534.325 ;
        RECT 171.310 530.160 176.910 534.325 ;
        RECT 177.750 530.160 183.350 534.325 ;
        RECT 184.190 530.160 189.790 534.325 ;
        RECT 190.630 530.160 196.230 534.325 ;
        RECT 197.070 530.160 202.670 534.325 ;
        RECT 203.510 530.160 209.110 534.325 ;
        RECT 209.950 530.160 215.550 534.325 ;
        RECT 216.390 530.160 221.990 534.325 ;
        RECT 222.830 530.160 228.430 534.325 ;
        RECT 229.270 530.160 234.870 534.325 ;
        RECT 235.710 530.160 241.310 534.325 ;
        RECT 242.150 530.160 247.750 534.325 ;
        RECT 248.590 530.160 254.190 534.325 ;
        RECT 255.030 530.160 260.630 534.325 ;
        RECT 261.470 530.160 267.070 534.325 ;
        RECT 267.910 530.160 273.510 534.325 ;
        RECT 274.350 530.160 279.950 534.325 ;
        RECT 280.790 530.160 286.390 534.325 ;
        RECT 287.230 530.160 292.830 534.325 ;
        RECT 293.670 530.160 299.270 534.325 ;
        RECT 300.110 530.160 305.710 534.325 ;
        RECT 306.550 530.160 312.150 534.325 ;
        RECT 312.990 530.160 318.590 534.325 ;
        RECT 319.430 530.160 325.030 534.325 ;
        RECT 325.870 530.160 331.470 534.325 ;
        RECT 332.310 530.160 337.910 534.325 ;
        RECT 338.750 530.160 344.350 534.325 ;
        RECT 345.190 530.160 350.790 534.325 ;
        RECT 351.630 530.160 357.230 534.325 ;
        RECT 358.070 530.160 363.670 534.325 ;
        RECT 364.510 530.160 370.110 534.325 ;
        RECT 370.950 530.160 376.550 534.325 ;
        RECT 377.390 530.160 382.990 534.325 ;
        RECT 383.830 530.160 389.430 534.325 ;
        RECT 390.270 530.160 395.870 534.325 ;
        RECT 396.710 530.160 402.310 534.325 ;
        RECT 403.150 530.160 408.750 534.325 ;
        RECT 409.590 530.160 415.190 534.325 ;
        RECT 416.030 530.160 421.630 534.325 ;
        RECT 422.470 530.160 428.070 534.325 ;
        RECT 428.910 530.160 434.510 534.325 ;
        RECT 435.350 530.160 440.950 534.325 ;
        RECT 441.790 530.160 447.390 534.325 ;
        RECT 448.230 530.160 453.830 534.325 ;
        RECT 454.670 530.160 460.270 534.325 ;
        RECT 461.110 530.160 466.710 534.325 ;
        RECT 467.550 530.160 473.150 534.325 ;
        RECT 473.990 530.160 479.590 534.325 ;
        RECT 480.430 530.160 486.030 534.325 ;
        RECT 486.870 530.160 492.470 534.325 ;
        RECT 493.310 530.160 498.910 534.325 ;
        RECT 499.750 530.160 505.350 534.325 ;
        RECT 506.190 530.160 511.790 534.325 ;
        RECT 512.630 530.160 518.230 534.325 ;
        RECT 519.070 530.160 521.450 534.325 ;
        RECT 0.100 4.280 522.000 530.160 ;
        RECT 0.650 0.155 3.030 4.280 ;
        RECT 3.870 0.155 9.470 4.280 ;
        RECT 10.310 0.155 15.910 4.280 ;
        RECT 16.750 0.155 22.350 4.280 ;
        RECT 23.190 0.155 28.790 4.280 ;
        RECT 29.630 0.155 35.230 4.280 ;
        RECT 36.070 0.155 41.670 4.280 ;
        RECT 42.510 0.155 48.110 4.280 ;
        RECT 48.950 0.155 54.550 4.280 ;
        RECT 55.390 0.155 60.990 4.280 ;
        RECT 61.830 0.155 67.430 4.280 ;
        RECT 68.270 0.155 73.870 4.280 ;
        RECT 74.710 0.155 80.310 4.280 ;
        RECT 81.150 0.155 86.750 4.280 ;
        RECT 87.590 0.155 93.190 4.280 ;
        RECT 94.030 0.155 99.630 4.280 ;
        RECT 100.470 0.155 106.070 4.280 ;
        RECT 106.910 0.155 112.510 4.280 ;
        RECT 113.350 0.155 118.950 4.280 ;
        RECT 119.790 0.155 125.390 4.280 ;
        RECT 126.230 0.155 131.830 4.280 ;
        RECT 132.670 0.155 138.270 4.280 ;
        RECT 139.110 0.155 144.710 4.280 ;
        RECT 145.550 0.155 151.150 4.280 ;
        RECT 151.990 0.155 157.590 4.280 ;
        RECT 158.430 0.155 164.030 4.280 ;
        RECT 164.870 0.155 170.470 4.280 ;
        RECT 171.310 0.155 176.910 4.280 ;
        RECT 177.750 0.155 183.350 4.280 ;
        RECT 184.190 0.155 189.790 4.280 ;
        RECT 190.630 0.155 196.230 4.280 ;
        RECT 197.070 0.155 202.670 4.280 ;
        RECT 203.510 0.155 209.110 4.280 ;
        RECT 209.950 0.155 215.550 4.280 ;
        RECT 216.390 0.155 221.990 4.280 ;
        RECT 222.830 0.155 228.430 4.280 ;
        RECT 229.270 0.155 234.870 4.280 ;
        RECT 235.710 0.155 241.310 4.280 ;
        RECT 242.150 0.155 247.750 4.280 ;
        RECT 248.590 0.155 254.190 4.280 ;
        RECT 255.030 0.155 260.630 4.280 ;
        RECT 261.470 0.155 267.070 4.280 ;
        RECT 267.910 0.155 273.510 4.280 ;
        RECT 274.350 0.155 279.950 4.280 ;
        RECT 280.790 0.155 286.390 4.280 ;
        RECT 287.230 0.155 292.830 4.280 ;
        RECT 293.670 0.155 299.270 4.280 ;
        RECT 300.110 0.155 305.710 4.280 ;
        RECT 306.550 0.155 312.150 4.280 ;
        RECT 312.990 0.155 318.590 4.280 ;
        RECT 319.430 0.155 325.030 4.280 ;
        RECT 325.870 0.155 331.470 4.280 ;
        RECT 332.310 0.155 337.910 4.280 ;
        RECT 338.750 0.155 344.350 4.280 ;
        RECT 345.190 0.155 350.790 4.280 ;
        RECT 351.630 0.155 357.230 4.280 ;
        RECT 358.070 0.155 363.670 4.280 ;
        RECT 364.510 0.155 370.110 4.280 ;
        RECT 370.950 0.155 376.550 4.280 ;
        RECT 377.390 0.155 382.990 4.280 ;
        RECT 383.830 0.155 389.430 4.280 ;
        RECT 390.270 0.155 395.870 4.280 ;
        RECT 396.710 0.155 402.310 4.280 ;
        RECT 403.150 0.155 408.750 4.280 ;
        RECT 409.590 0.155 415.190 4.280 ;
        RECT 416.030 0.155 421.630 4.280 ;
        RECT 422.470 0.155 428.070 4.280 ;
        RECT 428.910 0.155 434.510 4.280 ;
        RECT 435.350 0.155 440.950 4.280 ;
        RECT 441.790 0.155 447.390 4.280 ;
        RECT 448.230 0.155 453.830 4.280 ;
        RECT 454.670 0.155 460.270 4.280 ;
        RECT 461.110 0.155 466.710 4.280 ;
        RECT 467.550 0.155 473.150 4.280 ;
        RECT 473.990 0.155 479.590 4.280 ;
        RECT 480.430 0.155 486.030 4.280 ;
        RECT 486.870 0.155 492.470 4.280 ;
        RECT 493.310 0.155 498.910 4.280 ;
        RECT 499.750 0.155 505.350 4.280 ;
        RECT 506.190 0.155 511.790 4.280 ;
        RECT 512.630 0.155 518.230 4.280 ;
        RECT 519.070 0.155 522.000 4.280 ;
      LAYER met3 ;
        RECT 4.400 533.440 519.720 534.305 ;
        RECT 3.990 531.440 519.720 533.440 ;
        RECT 3.990 530.040 519.320 531.440 ;
        RECT 3.990 528.040 519.720 530.040 ;
        RECT 4.400 526.640 519.720 528.040 ;
        RECT 3.990 524.640 519.720 526.640 ;
        RECT 3.990 523.240 519.320 524.640 ;
        RECT 3.990 521.240 519.720 523.240 ;
        RECT 4.400 519.840 519.720 521.240 ;
        RECT 3.990 517.840 519.720 519.840 ;
        RECT 3.990 516.440 519.320 517.840 ;
        RECT 3.990 514.440 519.720 516.440 ;
        RECT 4.400 513.040 519.720 514.440 ;
        RECT 3.990 511.040 519.720 513.040 ;
        RECT 3.990 509.640 519.320 511.040 ;
        RECT 3.990 507.640 519.720 509.640 ;
        RECT 4.400 506.240 519.720 507.640 ;
        RECT 3.990 504.240 519.720 506.240 ;
        RECT 3.990 502.840 519.320 504.240 ;
        RECT 3.990 500.840 519.720 502.840 ;
        RECT 4.400 499.440 519.720 500.840 ;
        RECT 3.990 497.440 519.720 499.440 ;
        RECT 3.990 496.040 519.320 497.440 ;
        RECT 3.990 494.040 519.720 496.040 ;
        RECT 4.400 492.640 519.720 494.040 ;
        RECT 3.990 490.640 519.720 492.640 ;
        RECT 3.990 489.240 519.320 490.640 ;
        RECT 3.990 487.240 519.720 489.240 ;
        RECT 4.400 485.840 519.720 487.240 ;
        RECT 3.990 483.840 519.720 485.840 ;
        RECT 3.990 482.440 519.320 483.840 ;
        RECT 3.990 480.440 519.720 482.440 ;
        RECT 4.400 479.040 519.720 480.440 ;
        RECT 3.990 477.040 519.720 479.040 ;
        RECT 3.990 475.640 519.320 477.040 ;
        RECT 3.990 473.640 519.720 475.640 ;
        RECT 4.400 472.240 519.720 473.640 ;
        RECT 3.990 470.240 519.720 472.240 ;
        RECT 3.990 468.840 519.320 470.240 ;
        RECT 3.990 466.840 519.720 468.840 ;
        RECT 4.400 465.440 519.720 466.840 ;
        RECT 3.990 463.440 519.720 465.440 ;
        RECT 3.990 462.040 519.320 463.440 ;
        RECT 3.990 460.040 519.720 462.040 ;
        RECT 4.400 458.640 519.720 460.040 ;
        RECT 3.990 456.640 519.720 458.640 ;
        RECT 3.990 455.240 519.320 456.640 ;
        RECT 3.990 453.240 519.720 455.240 ;
        RECT 4.400 451.840 519.720 453.240 ;
        RECT 3.990 449.840 519.720 451.840 ;
        RECT 3.990 448.440 519.320 449.840 ;
        RECT 3.990 446.440 519.720 448.440 ;
        RECT 4.400 445.040 519.720 446.440 ;
        RECT 3.990 443.040 519.720 445.040 ;
        RECT 3.990 441.640 519.320 443.040 ;
        RECT 3.990 439.640 519.720 441.640 ;
        RECT 4.400 438.240 519.720 439.640 ;
        RECT 3.990 436.240 519.720 438.240 ;
        RECT 3.990 434.840 519.320 436.240 ;
        RECT 3.990 432.840 519.720 434.840 ;
        RECT 4.400 431.440 519.720 432.840 ;
        RECT 3.990 429.440 519.720 431.440 ;
        RECT 3.990 428.040 519.320 429.440 ;
        RECT 3.990 426.040 519.720 428.040 ;
        RECT 4.400 424.640 519.720 426.040 ;
        RECT 3.990 422.640 519.720 424.640 ;
        RECT 3.990 421.240 519.320 422.640 ;
        RECT 3.990 419.240 519.720 421.240 ;
        RECT 4.400 417.840 519.720 419.240 ;
        RECT 3.990 415.840 519.720 417.840 ;
        RECT 3.990 414.440 519.320 415.840 ;
        RECT 3.990 412.440 519.720 414.440 ;
        RECT 4.400 411.040 519.720 412.440 ;
        RECT 3.990 409.040 519.720 411.040 ;
        RECT 3.990 407.640 519.320 409.040 ;
        RECT 3.990 405.640 519.720 407.640 ;
        RECT 4.400 404.240 519.720 405.640 ;
        RECT 3.990 402.240 519.720 404.240 ;
        RECT 3.990 400.840 519.320 402.240 ;
        RECT 3.990 398.840 519.720 400.840 ;
        RECT 4.400 397.440 519.720 398.840 ;
        RECT 3.990 395.440 519.720 397.440 ;
        RECT 3.990 394.040 519.320 395.440 ;
        RECT 3.990 392.040 519.720 394.040 ;
        RECT 4.400 390.640 519.720 392.040 ;
        RECT 3.990 388.640 519.720 390.640 ;
        RECT 3.990 387.240 519.320 388.640 ;
        RECT 3.990 385.240 519.720 387.240 ;
        RECT 4.400 383.840 519.720 385.240 ;
        RECT 3.990 381.840 519.720 383.840 ;
        RECT 3.990 380.440 519.320 381.840 ;
        RECT 3.990 378.440 519.720 380.440 ;
        RECT 4.400 377.040 519.720 378.440 ;
        RECT 3.990 375.040 519.720 377.040 ;
        RECT 3.990 373.640 519.320 375.040 ;
        RECT 3.990 371.640 519.720 373.640 ;
        RECT 4.400 370.240 519.720 371.640 ;
        RECT 3.990 368.240 519.720 370.240 ;
        RECT 3.990 366.840 519.320 368.240 ;
        RECT 3.990 364.840 519.720 366.840 ;
        RECT 4.400 363.440 519.720 364.840 ;
        RECT 3.990 361.440 519.720 363.440 ;
        RECT 3.990 360.040 519.320 361.440 ;
        RECT 3.990 358.040 519.720 360.040 ;
        RECT 4.400 356.640 519.720 358.040 ;
        RECT 3.990 354.640 519.720 356.640 ;
        RECT 3.990 353.240 519.320 354.640 ;
        RECT 3.990 351.240 519.720 353.240 ;
        RECT 4.400 349.840 519.720 351.240 ;
        RECT 3.990 347.840 519.720 349.840 ;
        RECT 3.990 346.440 519.320 347.840 ;
        RECT 3.990 344.440 519.720 346.440 ;
        RECT 4.400 343.040 519.720 344.440 ;
        RECT 3.990 341.040 519.720 343.040 ;
        RECT 3.990 339.640 519.320 341.040 ;
        RECT 3.990 337.640 519.720 339.640 ;
        RECT 4.400 336.240 519.720 337.640 ;
        RECT 3.990 334.240 519.720 336.240 ;
        RECT 3.990 332.840 519.320 334.240 ;
        RECT 3.990 330.840 519.720 332.840 ;
        RECT 4.400 329.440 519.720 330.840 ;
        RECT 3.990 327.440 519.720 329.440 ;
        RECT 3.990 326.040 519.320 327.440 ;
        RECT 3.990 324.040 519.720 326.040 ;
        RECT 4.400 322.640 519.720 324.040 ;
        RECT 3.990 320.640 519.720 322.640 ;
        RECT 3.990 319.240 519.320 320.640 ;
        RECT 3.990 317.240 519.720 319.240 ;
        RECT 4.400 315.840 519.720 317.240 ;
        RECT 3.990 313.840 519.720 315.840 ;
        RECT 3.990 312.440 519.320 313.840 ;
        RECT 3.990 310.440 519.720 312.440 ;
        RECT 4.400 309.040 519.720 310.440 ;
        RECT 3.990 307.040 519.720 309.040 ;
        RECT 3.990 305.640 519.320 307.040 ;
        RECT 3.990 303.640 519.720 305.640 ;
        RECT 4.400 302.240 519.720 303.640 ;
        RECT 3.990 300.240 519.720 302.240 ;
        RECT 3.990 298.840 519.320 300.240 ;
        RECT 3.990 296.840 519.720 298.840 ;
        RECT 4.400 295.440 519.720 296.840 ;
        RECT 3.990 293.440 519.720 295.440 ;
        RECT 3.990 292.040 519.320 293.440 ;
        RECT 3.990 290.040 519.720 292.040 ;
        RECT 4.400 288.640 519.720 290.040 ;
        RECT 3.990 286.640 519.720 288.640 ;
        RECT 3.990 285.240 519.320 286.640 ;
        RECT 3.990 283.240 519.720 285.240 ;
        RECT 4.400 281.840 519.720 283.240 ;
        RECT 3.990 279.840 519.720 281.840 ;
        RECT 3.990 278.440 519.320 279.840 ;
        RECT 3.990 276.440 519.720 278.440 ;
        RECT 4.400 275.040 519.720 276.440 ;
        RECT 3.990 273.040 519.720 275.040 ;
        RECT 3.990 271.640 519.320 273.040 ;
        RECT 3.990 269.640 519.720 271.640 ;
        RECT 4.400 268.240 519.720 269.640 ;
        RECT 3.990 266.240 519.720 268.240 ;
        RECT 3.990 264.840 519.320 266.240 ;
        RECT 3.990 262.840 519.720 264.840 ;
        RECT 4.400 261.440 519.720 262.840 ;
        RECT 3.990 259.440 519.720 261.440 ;
        RECT 3.990 258.040 519.320 259.440 ;
        RECT 3.990 256.040 519.720 258.040 ;
        RECT 4.400 254.640 519.720 256.040 ;
        RECT 3.990 252.640 519.720 254.640 ;
        RECT 3.990 251.240 519.320 252.640 ;
        RECT 3.990 249.240 519.720 251.240 ;
        RECT 4.400 247.840 519.720 249.240 ;
        RECT 3.990 245.840 519.720 247.840 ;
        RECT 3.990 244.440 519.320 245.840 ;
        RECT 3.990 242.440 519.720 244.440 ;
        RECT 4.400 241.040 519.720 242.440 ;
        RECT 3.990 239.040 519.720 241.040 ;
        RECT 3.990 237.640 519.320 239.040 ;
        RECT 3.990 235.640 519.720 237.640 ;
        RECT 4.400 234.240 519.720 235.640 ;
        RECT 3.990 232.240 519.720 234.240 ;
        RECT 3.990 230.840 519.320 232.240 ;
        RECT 3.990 228.840 519.720 230.840 ;
        RECT 4.400 227.440 519.720 228.840 ;
        RECT 3.990 225.440 519.720 227.440 ;
        RECT 3.990 224.040 519.320 225.440 ;
        RECT 3.990 222.040 519.720 224.040 ;
        RECT 4.400 220.640 519.720 222.040 ;
        RECT 3.990 218.640 519.720 220.640 ;
        RECT 3.990 217.240 519.320 218.640 ;
        RECT 3.990 215.240 519.720 217.240 ;
        RECT 4.400 213.840 519.720 215.240 ;
        RECT 3.990 211.840 519.720 213.840 ;
        RECT 3.990 210.440 519.320 211.840 ;
        RECT 3.990 208.440 519.720 210.440 ;
        RECT 4.400 207.040 519.720 208.440 ;
        RECT 3.990 205.040 519.720 207.040 ;
        RECT 3.990 203.640 519.320 205.040 ;
        RECT 3.990 201.640 519.720 203.640 ;
        RECT 4.400 200.240 519.720 201.640 ;
        RECT 3.990 198.240 519.720 200.240 ;
        RECT 3.990 196.840 519.320 198.240 ;
        RECT 3.990 194.840 519.720 196.840 ;
        RECT 4.400 193.440 519.720 194.840 ;
        RECT 3.990 191.440 519.720 193.440 ;
        RECT 3.990 190.040 519.320 191.440 ;
        RECT 3.990 188.040 519.720 190.040 ;
        RECT 4.400 186.640 519.720 188.040 ;
        RECT 3.990 184.640 519.720 186.640 ;
        RECT 3.990 183.240 519.320 184.640 ;
        RECT 3.990 181.240 519.720 183.240 ;
        RECT 4.400 179.840 519.720 181.240 ;
        RECT 3.990 177.840 519.720 179.840 ;
        RECT 3.990 176.440 519.320 177.840 ;
        RECT 3.990 174.440 519.720 176.440 ;
        RECT 4.400 173.040 519.720 174.440 ;
        RECT 3.990 171.040 519.720 173.040 ;
        RECT 3.990 169.640 519.320 171.040 ;
        RECT 3.990 167.640 519.720 169.640 ;
        RECT 4.400 166.240 519.720 167.640 ;
        RECT 3.990 164.240 519.720 166.240 ;
        RECT 3.990 162.840 519.320 164.240 ;
        RECT 3.990 160.840 519.720 162.840 ;
        RECT 4.400 159.440 519.720 160.840 ;
        RECT 3.990 157.440 519.720 159.440 ;
        RECT 3.990 156.040 519.320 157.440 ;
        RECT 3.990 154.040 519.720 156.040 ;
        RECT 4.400 152.640 519.720 154.040 ;
        RECT 3.990 150.640 519.720 152.640 ;
        RECT 3.990 149.240 519.320 150.640 ;
        RECT 3.990 147.240 519.720 149.240 ;
        RECT 4.400 145.840 519.720 147.240 ;
        RECT 3.990 143.840 519.720 145.840 ;
        RECT 3.990 142.440 519.320 143.840 ;
        RECT 3.990 140.440 519.720 142.440 ;
        RECT 4.400 139.040 519.720 140.440 ;
        RECT 3.990 137.040 519.720 139.040 ;
        RECT 3.990 135.640 519.320 137.040 ;
        RECT 3.990 133.640 519.720 135.640 ;
        RECT 4.400 132.240 519.720 133.640 ;
        RECT 3.990 130.240 519.720 132.240 ;
        RECT 3.990 128.840 519.320 130.240 ;
        RECT 3.990 126.840 519.720 128.840 ;
        RECT 4.400 125.440 519.720 126.840 ;
        RECT 3.990 123.440 519.720 125.440 ;
        RECT 3.990 122.040 519.320 123.440 ;
        RECT 3.990 120.040 519.720 122.040 ;
        RECT 4.400 118.640 519.720 120.040 ;
        RECT 3.990 116.640 519.720 118.640 ;
        RECT 3.990 115.240 519.320 116.640 ;
        RECT 3.990 113.240 519.720 115.240 ;
        RECT 4.400 111.840 519.720 113.240 ;
        RECT 3.990 109.840 519.720 111.840 ;
        RECT 3.990 108.440 519.320 109.840 ;
        RECT 3.990 106.440 519.720 108.440 ;
        RECT 4.400 105.040 519.720 106.440 ;
        RECT 3.990 103.040 519.720 105.040 ;
        RECT 3.990 101.640 519.320 103.040 ;
        RECT 3.990 99.640 519.720 101.640 ;
        RECT 4.400 98.240 519.720 99.640 ;
        RECT 3.990 96.240 519.720 98.240 ;
        RECT 3.990 94.840 519.320 96.240 ;
        RECT 3.990 92.840 519.720 94.840 ;
        RECT 4.400 91.440 519.720 92.840 ;
        RECT 3.990 89.440 519.720 91.440 ;
        RECT 3.990 88.040 519.320 89.440 ;
        RECT 3.990 86.040 519.720 88.040 ;
        RECT 4.400 84.640 519.720 86.040 ;
        RECT 3.990 82.640 519.720 84.640 ;
        RECT 3.990 81.240 519.320 82.640 ;
        RECT 3.990 79.240 519.720 81.240 ;
        RECT 4.400 77.840 519.720 79.240 ;
        RECT 3.990 75.840 519.720 77.840 ;
        RECT 3.990 74.440 519.320 75.840 ;
        RECT 3.990 72.440 519.720 74.440 ;
        RECT 4.400 71.040 519.720 72.440 ;
        RECT 3.990 69.040 519.720 71.040 ;
        RECT 3.990 67.640 519.320 69.040 ;
        RECT 3.990 65.640 519.720 67.640 ;
        RECT 4.400 64.240 519.720 65.640 ;
        RECT 3.990 62.240 519.720 64.240 ;
        RECT 3.990 60.840 519.320 62.240 ;
        RECT 3.990 58.840 519.720 60.840 ;
        RECT 4.400 57.440 519.720 58.840 ;
        RECT 3.990 55.440 519.720 57.440 ;
        RECT 3.990 54.040 519.320 55.440 ;
        RECT 3.990 52.040 519.720 54.040 ;
        RECT 4.400 50.640 519.720 52.040 ;
        RECT 3.990 48.640 519.720 50.640 ;
        RECT 3.990 47.240 519.320 48.640 ;
        RECT 3.990 45.240 519.720 47.240 ;
        RECT 4.400 43.840 519.720 45.240 ;
        RECT 3.990 41.840 519.720 43.840 ;
        RECT 3.990 40.440 519.320 41.840 ;
        RECT 3.990 38.440 519.720 40.440 ;
        RECT 4.400 37.040 519.720 38.440 ;
        RECT 3.990 35.040 519.720 37.040 ;
        RECT 3.990 33.640 519.320 35.040 ;
        RECT 3.990 31.640 519.720 33.640 ;
        RECT 4.400 30.240 519.720 31.640 ;
        RECT 3.990 28.240 519.720 30.240 ;
        RECT 3.990 26.840 519.320 28.240 ;
        RECT 3.990 24.840 519.720 26.840 ;
        RECT 4.400 23.440 519.720 24.840 ;
        RECT 3.990 21.440 519.720 23.440 ;
        RECT 3.990 20.040 519.320 21.440 ;
        RECT 3.990 18.040 519.720 20.040 ;
        RECT 4.400 16.640 519.720 18.040 ;
        RECT 3.990 14.640 519.720 16.640 ;
        RECT 3.990 13.240 519.320 14.640 ;
        RECT 3.990 11.240 519.720 13.240 ;
        RECT 4.400 9.840 519.720 11.240 ;
        RECT 3.990 7.840 519.720 9.840 ;
        RECT 3.990 6.440 519.320 7.840 ;
        RECT 3.990 4.440 519.720 6.440 ;
        RECT 4.400 3.040 519.720 4.440 ;
        RECT 3.990 1.040 519.720 3.040 ;
        RECT 3.990 0.175 519.320 1.040 ;
      LAYER met4 ;
        RECT 7.655 10.240 20.640 521.385 ;
        RECT 23.040 10.240 23.940 521.385 ;
        RECT 26.340 10.240 174.240 521.385 ;
        RECT 176.640 10.240 177.540 521.385 ;
        RECT 179.940 10.240 327.840 521.385 ;
        RECT 330.240 10.240 331.140 521.385 ;
        RECT 333.540 10.240 481.440 521.385 ;
        RECT 483.840 10.240 484.740 521.385 ;
        RECT 487.140 10.240 509.385 521.385 ;
        RECT 7.655 8.335 509.385 10.240 ;
  END
END mm_sys_array
END LIBRARY

